VERSION 5.8 ;
BUSBITCHARS "[]" ;
DIVIDERCHAR "/" ;
UNITS
    DATABASE MICRONS 1000 ;
END UNITS

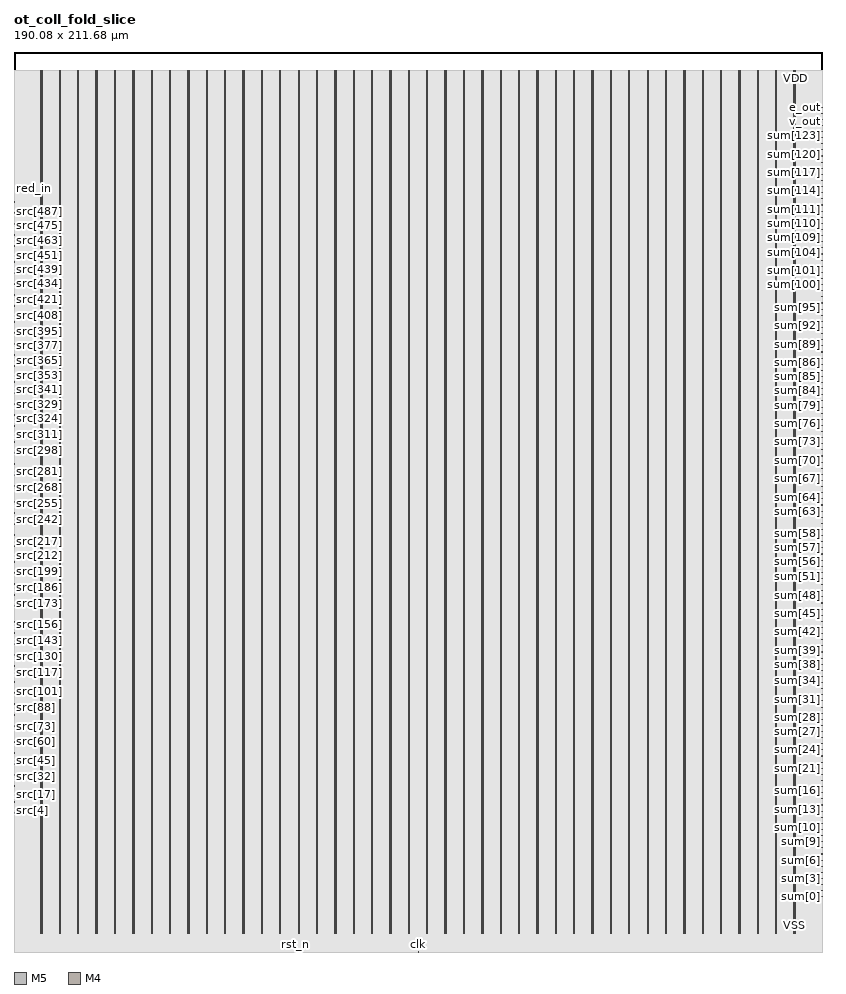
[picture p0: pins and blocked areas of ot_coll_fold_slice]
MACRO ot_coll_fold_slice
  FOREIGN ot_coll_fold_slice 0 0 ;
  CLASS BLOCK ;
  SIZE 190.08 BY 211.68 ;
  PIN clk
    DIRECTION INPUT ;
    USE SIGNAL ;
    PORT
      LAYER M5 ;
        RECT  95.04 0 95.064 0.084 ;
    END
  END clk
  PIN e_out
    DIRECTION OUTPUT ;
    USE SIGNAL ;
    PORT
      LAYER M4 ;
        RECT  189.996 198.72 190.08 198.744 ;
    END
  END e_out
  PIN red_in
    DIRECTION INPUT ;
    USE SIGNAL ;
    PORT
      LAYER M4 ;
        RECT  0 179.568 0.084 179.592 ;
    END
  END red_in
  PIN rst_n
    DIRECTION INPUT ;
    USE SIGNAL ;
    PORT
      LAYER M5 ;
        RECT  66.24 0 66.264 0.084 ;
    END
  END rst_n
  PIN src[0]
    DIRECTION INPUT ;
    USE SIGNAL ;
    PORT
      LAYER M4 ;
        RECT  0 32.112 0.084 32.136 ;
    END
  END src[0]
  PIN src[100]
    DIRECTION INPUT ;
    USE SIGNAL ;
    PORT
      LAYER M4 ;
        RECT  0 60.912 0.084 60.936 ;
    END
  END src[100]
  PIN src[101]
    DIRECTION INPUT ;
    USE SIGNAL ;
    PORT
      LAYER M4 ;
        RECT  0 61.2 0.084 61.224 ;
    END
  END src[101]
  PIN src[102]
    DIRECTION INPUT ;
    USE SIGNAL ;
    PORT
      LAYER M4 ;
        RECT  0 61.488 0.084 61.512 ;
    END
  END src[102]
  PIN src[103]
    DIRECTION INPUT ;
    USE SIGNAL ;
    PORT
      LAYER M4 ;
        RECT  0 61.776 0.084 61.8 ;
    END
  END src[103]
  PIN src[104]
    DIRECTION INPUT ;
    USE SIGNAL ;
    PORT
      LAYER M4 ;
        RECT  0 62.064 0.084 62.088 ;
    END
  END src[104]
  PIN src[105]
    DIRECTION INPUT ;
    USE SIGNAL ;
    PORT
      LAYER M4 ;
        RECT  0 62.352 0.084 62.376 ;
    END
  END src[105]
  PIN src[106]
    DIRECTION INPUT ;
    USE SIGNAL ;
    PORT
      LAYER M4 ;
        RECT  0 62.64 0.084 62.664 ;
    END
  END src[106]
  PIN src[107]
    DIRECTION INPUT ;
    USE SIGNAL ;
    PORT
      LAYER M4 ;
        RECT  0 62.928 0.084 62.952 ;
    END
  END src[107]
  PIN src[108]
    DIRECTION INPUT ;
    USE SIGNAL ;
    PORT
      LAYER M4 ;
        RECT  0 63.216 0.084 63.24 ;
    END
  END src[108]
  PIN src[109]
    DIRECTION INPUT ;
    USE SIGNAL ;
    PORT
      LAYER M4 ;
        RECT  0 63.504 0.084 63.528 ;
    END
  END src[109]
  PIN src[10]
    DIRECTION INPUT ;
    USE SIGNAL ;
    PORT
      LAYER M4 ;
        RECT  0 34.992 0.084 35.016 ;
    END
  END src[10]
  PIN src[110]
    DIRECTION INPUT ;
    USE SIGNAL ;
    PORT
      LAYER M4 ;
        RECT  0 63.792 0.084 63.816 ;
    END
  END src[110]
  PIN src[111]
    DIRECTION INPUT ;
    USE SIGNAL ;
    PORT
      LAYER M4 ;
        RECT  0 64.08 0.084 64.104 ;
    END
  END src[111]
  PIN src[112]
    DIRECTION INPUT ;
    USE SIGNAL ;
    PORT
      LAYER M4 ;
        RECT  0 64.368 0.084 64.392 ;
    END
  END src[112]
  PIN src[113]
    DIRECTION INPUT ;
    USE SIGNAL ;
    PORT
      LAYER M4 ;
        RECT  0 64.656 0.084 64.68 ;
    END
  END src[113]
  PIN src[114]
    DIRECTION INPUT ;
    USE SIGNAL ;
    PORT
      LAYER M4 ;
        RECT  0 64.944 0.084 64.968 ;
    END
  END src[114]
  PIN src[115]
    DIRECTION INPUT ;
    USE SIGNAL ;
    PORT
      LAYER M4 ;
        RECT  0 65.232 0.084 65.256 ;
    END
  END src[115]
  PIN src[116]
    DIRECTION INPUT ;
    USE SIGNAL ;
    PORT
      LAYER M4 ;
        RECT  0 65.52 0.084 65.544 ;
    END
  END src[116]
  PIN src[117]
    DIRECTION INPUT ;
    USE SIGNAL ;
    PORT
      LAYER M4 ;
        RECT  0 65.808 0.084 65.832 ;
    END
  END src[117]
  PIN src[118]
    DIRECTION INPUT ;
    USE SIGNAL ;
    PORT
      LAYER M4 ;
        RECT  0 66.096 0.084 66.12 ;
    END
  END src[118]
  PIN src[119]
    DIRECTION INPUT ;
    USE SIGNAL ;
    PORT
      LAYER M4 ;
        RECT  0 66.384 0.084 66.408 ;
    END
  END src[119]
  PIN src[11]
    DIRECTION INPUT ;
    USE SIGNAL ;
    PORT
      LAYER M4 ;
        RECT  0 35.28 0.084 35.304 ;
    END
  END src[11]
  PIN src[120]
    DIRECTION INPUT ;
    USE SIGNAL ;
    PORT
      LAYER M4 ;
        RECT  0 66.672 0.084 66.696 ;
    END
  END src[120]
  PIN src[121]
    DIRECTION INPUT ;
    USE SIGNAL ;
    PORT
      LAYER M4 ;
        RECT  0 66.96 0.084 66.984 ;
    END
  END src[121]
  PIN src[122]
    DIRECTION INPUT ;
    USE SIGNAL ;
    PORT
      LAYER M4 ;
        RECT  0 67.248 0.084 67.272 ;
    END
  END src[122]
  PIN src[123]
    DIRECTION INPUT ;
    USE SIGNAL ;
    PORT
      LAYER M4 ;
        RECT  0 67.536 0.084 67.56 ;
    END
  END src[123]
  PIN src[124]
    DIRECTION INPUT ;
    USE SIGNAL ;
    PORT
      LAYER M4 ;
        RECT  0 67.824 0.084 67.848 ;
    END
  END src[124]
  PIN src[125]
    DIRECTION INPUT ;
    USE SIGNAL ;
    PORT
      LAYER M4 ;
        RECT  0 68.112 0.084 68.136 ;
    END
  END src[125]
  PIN src[126]
    DIRECTION INPUT ;
    USE SIGNAL ;
    PORT
      LAYER M4 ;
        RECT  0 68.4 0.084 68.424 ;
    END
  END src[126]
  PIN src[127]
    DIRECTION INPUT ;
    USE SIGNAL ;
    PORT
      LAYER M4 ;
        RECT  0 68.688 0.084 68.712 ;
    END
  END src[127]
  PIN src[128]
    DIRECTION INPUT ;
    USE SIGNAL ;
    PORT
      LAYER M4 ;
        RECT  0 68.976 0.084 69 ;
    END
  END src[128]
  PIN src[129]
    DIRECTION INPUT ;
    USE SIGNAL ;
    PORT
      LAYER M4 ;
        RECT  0 69.264 0.084 69.288 ;
    END
  END src[129]
  PIN src[12]
    DIRECTION INPUT ;
    USE SIGNAL ;
    PORT
      LAYER M4 ;
        RECT  0 35.568 0.084 35.592 ;
    END
  END src[12]
  PIN src[130]
    DIRECTION INPUT ;
    USE SIGNAL ;
    PORT
      LAYER M4 ;
        RECT  0 69.552 0.084 69.576 ;
    END
  END src[130]
  PIN src[131]
    DIRECTION INPUT ;
    USE SIGNAL ;
    PORT
      LAYER M4 ;
        RECT  0 69.84 0.084 69.864 ;
    END
  END src[131]
  PIN src[132]
    DIRECTION INPUT ;
    USE SIGNAL ;
    PORT
      LAYER M4 ;
        RECT  0 70.128 0.084 70.152 ;
    END
  END src[132]
  PIN src[133]
    DIRECTION INPUT ;
    USE SIGNAL ;
    PORT
      LAYER M4 ;
        RECT  0 70.416 0.084 70.44 ;
    END
  END src[133]
  PIN src[134]
    DIRECTION INPUT ;
    USE SIGNAL ;
    PORT
      LAYER M4 ;
        RECT  0 70.704 0.084 70.728 ;
    END
  END src[134]
  PIN src[135]
    DIRECTION INPUT ;
    USE SIGNAL ;
    PORT
      LAYER M4 ;
        RECT  0 70.992 0.084 71.016 ;
    END
  END src[135]
  PIN src[136]
    DIRECTION INPUT ;
    USE SIGNAL ;
    PORT
      LAYER M4 ;
        RECT  0 71.28 0.084 71.304 ;
    END
  END src[136]
  PIN src[137]
    DIRECTION INPUT ;
    USE SIGNAL ;
    PORT
      LAYER M4 ;
        RECT  0 71.568 0.084 71.592 ;
    END
  END src[137]
  PIN src[138]
    DIRECTION INPUT ;
    USE SIGNAL ;
    PORT
      LAYER M4 ;
        RECT  0 71.856 0.084 71.88 ;
    END
  END src[138]
  PIN src[139]
    DIRECTION INPUT ;
    USE SIGNAL ;
    PORT
      LAYER M4 ;
        RECT  0 72.144 0.084 72.168 ;
    END
  END src[139]
  PIN src[13]
    DIRECTION INPUT ;
    USE SIGNAL ;
    PORT
      LAYER M4 ;
        RECT  0 35.856 0.084 35.88 ;
    END
  END src[13]
  PIN src[140]
    DIRECTION INPUT ;
    USE SIGNAL ;
    PORT
      LAYER M4 ;
        RECT  0 72.432 0.084 72.456 ;
    END
  END src[140]
  PIN src[141]
    DIRECTION INPUT ;
    USE SIGNAL ;
    PORT
      LAYER M4 ;
        RECT  0 72.72 0.084 72.744 ;
    END
  END src[141]
  PIN src[142]
    DIRECTION INPUT ;
    USE SIGNAL ;
    PORT
      LAYER M4 ;
        RECT  0 73.008 0.084 73.032 ;
    END
  END src[142]
  PIN src[143]
    DIRECTION INPUT ;
    USE SIGNAL ;
    PORT
      LAYER M4 ;
        RECT  0 73.296 0.084 73.32 ;
    END
  END src[143]
  PIN src[144]
    DIRECTION INPUT ;
    USE SIGNAL ;
    PORT
      LAYER M4 ;
        RECT  0 73.584 0.084 73.608 ;
    END
  END src[144]
  PIN src[145]
    DIRECTION INPUT ;
    USE SIGNAL ;
    PORT
      LAYER M4 ;
        RECT  0 73.872 0.084 73.896 ;
    END
  END src[145]
  PIN src[146]
    DIRECTION INPUT ;
    USE SIGNAL ;
    PORT
      LAYER M4 ;
        RECT  0 74.16 0.084 74.184 ;
    END
  END src[146]
  PIN src[147]
    DIRECTION INPUT ;
    USE SIGNAL ;
    PORT
      LAYER M4 ;
        RECT  0 74.448 0.084 74.472 ;
    END
  END src[147]
  PIN src[148]
    DIRECTION INPUT ;
    USE SIGNAL ;
    PORT
      LAYER M4 ;
        RECT  0 74.736 0.084 74.76 ;
    END
  END src[148]
  PIN src[149]
    DIRECTION INPUT ;
    USE SIGNAL ;
    PORT
      LAYER M4 ;
        RECT  0 75.024 0.084 75.048 ;
    END
  END src[149]
  PIN src[14]
    DIRECTION INPUT ;
    USE SIGNAL ;
    PORT
      LAYER M4 ;
        RECT  0 36.144 0.084 36.168 ;
    END
  END src[14]
  PIN src[150]
    DIRECTION INPUT ;
    USE SIGNAL ;
    PORT
      LAYER M4 ;
        RECT  0 75.312 0.084 75.336 ;
    END
  END src[150]
  PIN src[151]
    DIRECTION INPUT ;
    USE SIGNAL ;
    PORT
      LAYER M4 ;
        RECT  0 75.6 0.084 75.624 ;
    END
  END src[151]
  PIN src[152]
    DIRECTION INPUT ;
    USE SIGNAL ;
    PORT
      LAYER M4 ;
        RECT  0 75.888 0.084 75.912 ;
    END
  END src[152]
  PIN src[153]
    DIRECTION INPUT ;
    USE SIGNAL ;
    PORT
      LAYER M4 ;
        RECT  0 76.176 0.084 76.2 ;
    END
  END src[153]
  PIN src[154]
    DIRECTION INPUT ;
    USE SIGNAL ;
    PORT
      LAYER M4 ;
        RECT  0 76.464 0.084 76.488 ;
    END
  END src[154]
  PIN src[155]
    DIRECTION INPUT ;
    USE SIGNAL ;
    PORT
      LAYER M4 ;
        RECT  0 76.752 0.084 76.776 ;
    END
  END src[155]
  PIN src[156]
    DIRECTION INPUT ;
    USE SIGNAL ;
    PORT
      LAYER M4 ;
        RECT  0 77.04 0.084 77.064 ;
    END
  END src[156]
  PIN src[157]
    DIRECTION INPUT ;
    USE SIGNAL ;
    PORT
      LAYER M4 ;
        RECT  0 77.328 0.084 77.352 ;
    END
  END src[157]
  PIN src[158]
    DIRECTION INPUT ;
    USE SIGNAL ;
    PORT
      LAYER M4 ;
        RECT  0 77.616 0.084 77.64 ;
    END
  END src[158]
  PIN src[159]
    DIRECTION INPUT ;
    USE SIGNAL ;
    PORT
      LAYER M4 ;
        RECT  0 77.904 0.084 77.928 ;
    END
  END src[159]
  PIN src[15]
    DIRECTION INPUT ;
    USE SIGNAL ;
    PORT
      LAYER M4 ;
        RECT  0 36.432 0.084 36.456 ;
    END
  END src[15]
  PIN src[160]
    DIRECTION INPUT ;
    USE SIGNAL ;
    PORT
      LAYER M4 ;
        RECT  0 78.192 0.084 78.216 ;
    END
  END src[160]
  PIN src[161]
    DIRECTION INPUT ;
    USE SIGNAL ;
    PORT
      LAYER M4 ;
        RECT  0 78.48 0.084 78.504 ;
    END
  END src[161]
  PIN src[162]
    DIRECTION INPUT ;
    USE SIGNAL ;
    PORT
      LAYER M4 ;
        RECT  0 78.768 0.084 78.792 ;
    END
  END src[162]
  PIN src[163]
    DIRECTION INPUT ;
    USE SIGNAL ;
    PORT
      LAYER M4 ;
        RECT  0 79.056 0.084 79.08 ;
    END
  END src[163]
  PIN src[164]
    DIRECTION INPUT ;
    USE SIGNAL ;
    PORT
      LAYER M4 ;
        RECT  0 79.344 0.084 79.368 ;
    END
  END src[164]
  PIN src[165]
    DIRECTION INPUT ;
    USE SIGNAL ;
    PORT
      LAYER M4 ;
        RECT  0 79.632 0.084 79.656 ;
    END
  END src[165]
  PIN src[166]
    DIRECTION INPUT ;
    USE SIGNAL ;
    PORT
      LAYER M4 ;
        RECT  0 79.92 0.084 79.944 ;
    END
  END src[166]
  PIN src[167]
    DIRECTION INPUT ;
    USE SIGNAL ;
    PORT
      LAYER M4 ;
        RECT  0 80.208 0.084 80.232 ;
    END
  END src[167]
  PIN src[168]
    DIRECTION INPUT ;
    USE SIGNAL ;
    PORT
      LAYER M4 ;
        RECT  0 80.496 0.084 80.52 ;
    END
  END src[168]
  PIN src[169]
    DIRECTION INPUT ;
    USE SIGNAL ;
    PORT
      LAYER M4 ;
        RECT  0 80.784 0.084 80.808 ;
    END
  END src[169]
  PIN src[16]
    DIRECTION INPUT ;
    USE SIGNAL ;
    PORT
      LAYER M4 ;
        RECT  0 36.72 0.084 36.744 ;
    END
  END src[16]
  PIN src[170]
    DIRECTION INPUT ;
    USE SIGNAL ;
    PORT
      LAYER M4 ;
        RECT  0 81.072 0.084 81.096 ;
    END
  END src[170]
  PIN src[171]
    DIRECTION INPUT ;
    USE SIGNAL ;
    PORT
      LAYER M4 ;
        RECT  0 81.36 0.084 81.384 ;
    END
  END src[171]
  PIN src[172]
    DIRECTION INPUT ;
    USE SIGNAL ;
    PORT
      LAYER M4 ;
        RECT  0 81.648 0.084 81.672 ;
    END
  END src[172]
  PIN src[173]
    DIRECTION INPUT ;
    USE SIGNAL ;
    PORT
      LAYER M4 ;
        RECT  0 81.936 0.084 81.96 ;
    END
  END src[173]
  PIN src[174]
    DIRECTION INPUT ;
    USE SIGNAL ;
    PORT
      LAYER M4 ;
        RECT  0 82.224 0.084 82.248 ;
    END
  END src[174]
  PIN src[175]
    DIRECTION INPUT ;
    USE SIGNAL ;
    PORT
      LAYER M4 ;
        RECT  0 82.512 0.084 82.536 ;
    END
  END src[175]
  PIN src[176]
    DIRECTION INPUT ;
    USE SIGNAL ;
    PORT
      LAYER M4 ;
        RECT  0 82.8 0.084 82.824 ;
    END
  END src[176]
  PIN src[177]
    DIRECTION INPUT ;
    USE SIGNAL ;
    PORT
      LAYER M4 ;
        RECT  0 83.088 0.084 83.112 ;
    END
  END src[177]
  PIN src[178]
    DIRECTION INPUT ;
    USE SIGNAL ;
    PORT
      LAYER M4 ;
        RECT  0 83.376 0.084 83.4 ;
    END
  END src[178]
  PIN src[179]
    DIRECTION INPUT ;
    USE SIGNAL ;
    PORT
      LAYER M4 ;
        RECT  0 83.664 0.084 83.688 ;
    END
  END src[179]
  PIN src[17]
    DIRECTION INPUT ;
    USE SIGNAL ;
    PORT
      LAYER M4 ;
        RECT  0 37.008 0.084 37.032 ;
    END
  END src[17]
  PIN src[180]
    DIRECTION INPUT ;
    USE SIGNAL ;
    PORT
      LAYER M4 ;
        RECT  0 83.952 0.084 83.976 ;
    END
  END src[180]
  PIN src[181]
    DIRECTION INPUT ;
    USE SIGNAL ;
    PORT
      LAYER M4 ;
        RECT  0 84.24 0.084 84.264 ;
    END
  END src[181]
  PIN src[182]
    DIRECTION INPUT ;
    USE SIGNAL ;
    PORT
      LAYER M4 ;
        RECT  0 84.528 0.084 84.552 ;
    END
  END src[182]
  PIN src[183]
    DIRECTION INPUT ;
    USE SIGNAL ;
    PORT
      LAYER M4 ;
        RECT  0 84.816 0.084 84.84 ;
    END
  END src[183]
  PIN src[184]
    DIRECTION INPUT ;
    USE SIGNAL ;
    PORT
      LAYER M4 ;
        RECT  0 85.104 0.084 85.128 ;
    END
  END src[184]
  PIN src[185]
    DIRECTION INPUT ;
    USE SIGNAL ;
    PORT
      LAYER M4 ;
        RECT  0 85.392 0.084 85.416 ;
    END
  END src[185]
  PIN src[186]
    DIRECTION INPUT ;
    USE SIGNAL ;
    PORT
      LAYER M4 ;
        RECT  0 85.68 0.084 85.704 ;
    END
  END src[186]
  PIN src[187]
    DIRECTION INPUT ;
    USE SIGNAL ;
    PORT
      LAYER M4 ;
        RECT  0 85.968 0.084 85.992 ;
    END
  END src[187]
  PIN src[188]
    DIRECTION INPUT ;
    USE SIGNAL ;
    PORT
      LAYER M4 ;
        RECT  0 86.256 0.084 86.28 ;
    END
  END src[188]
  PIN src[189]
    DIRECTION INPUT ;
    USE SIGNAL ;
    PORT
      LAYER M4 ;
        RECT  0 86.544 0.084 86.568 ;
    END
  END src[189]
  PIN src[18]
    DIRECTION INPUT ;
    USE SIGNAL ;
    PORT
      LAYER M4 ;
        RECT  0 37.296 0.084 37.32 ;
    END
  END src[18]
  PIN src[190]
    DIRECTION INPUT ;
    USE SIGNAL ;
    PORT
      LAYER M4 ;
        RECT  0 86.832 0.084 86.856 ;
    END
  END src[190]
  PIN src[191]
    DIRECTION INPUT ;
    USE SIGNAL ;
    PORT
      LAYER M4 ;
        RECT  0 87.12 0.084 87.144 ;
    END
  END src[191]
  PIN src[192]
    DIRECTION INPUT ;
    USE SIGNAL ;
    PORT
      LAYER M4 ;
        RECT  0 87.408 0.084 87.432 ;
    END
  END src[192]
  PIN src[193]
    DIRECTION INPUT ;
    USE SIGNAL ;
    PORT
      LAYER M4 ;
        RECT  0 87.696 0.084 87.72 ;
    END
  END src[193]
  PIN src[194]
    DIRECTION INPUT ;
    USE SIGNAL ;
    PORT
      LAYER M4 ;
        RECT  0 87.984 0.084 88.008 ;
    END
  END src[194]
  PIN src[195]
    DIRECTION INPUT ;
    USE SIGNAL ;
    PORT
      LAYER M4 ;
        RECT  0 88.272 0.084 88.296 ;
    END
  END src[195]
  PIN src[196]
    DIRECTION INPUT ;
    USE SIGNAL ;
    PORT
      LAYER M4 ;
        RECT  0 88.56 0.084 88.584 ;
    END
  END src[196]
  PIN src[197]
    DIRECTION INPUT ;
    USE SIGNAL ;
    PORT
      LAYER M4 ;
        RECT  0 88.848 0.084 88.872 ;
    END
  END src[197]
  PIN src[198]
    DIRECTION INPUT ;
    USE SIGNAL ;
    PORT
      LAYER M4 ;
        RECT  0 89.136 0.084 89.16 ;
    END
  END src[198]
  PIN src[199]
    DIRECTION INPUT ;
    USE SIGNAL ;
    PORT
      LAYER M4 ;
        RECT  0 89.424 0.084 89.448 ;
    END
  END src[199]
  PIN src[19]
    DIRECTION INPUT ;
    USE SIGNAL ;
    PORT
      LAYER M4 ;
        RECT  0 37.584 0.084 37.608 ;
    END
  END src[19]
  PIN src[1]
    DIRECTION INPUT ;
    USE SIGNAL ;
    PORT
      LAYER M4 ;
        RECT  0 32.4 0.084 32.424 ;
    END
  END src[1]
  PIN src[200]
    DIRECTION INPUT ;
    USE SIGNAL ;
    PORT
      LAYER M4 ;
        RECT  0 89.712 0.084 89.736 ;
    END
  END src[200]
  PIN src[201]
    DIRECTION INPUT ;
    USE SIGNAL ;
    PORT
      LAYER M4 ;
        RECT  0 90 0.084 90.024 ;
    END
  END src[201]
  PIN src[202]
    DIRECTION INPUT ;
    USE SIGNAL ;
    PORT
      LAYER M4 ;
        RECT  0 90.288 0.084 90.312 ;
    END
  END src[202]
  PIN src[203]
    DIRECTION INPUT ;
    USE SIGNAL ;
    PORT
      LAYER M4 ;
        RECT  0 90.576 0.084 90.6 ;
    END
  END src[203]
  PIN src[204]
    DIRECTION INPUT ;
    USE SIGNAL ;
    PORT
      LAYER M4 ;
        RECT  0 90.864 0.084 90.888 ;
    END
  END src[204]
  PIN src[205]
    DIRECTION INPUT ;
    USE SIGNAL ;
    PORT
      LAYER M4 ;
        RECT  0 91.152 0.084 91.176 ;
    END
  END src[205]
  PIN src[206]
    DIRECTION INPUT ;
    USE SIGNAL ;
    PORT
      LAYER M4 ;
        RECT  0 91.44 0.084 91.464 ;
    END
  END src[206]
  PIN src[207]
    DIRECTION INPUT ;
    USE SIGNAL ;
    PORT
      LAYER M4 ;
        RECT  0 91.728 0.084 91.752 ;
    END
  END src[207]
  PIN src[208]
    DIRECTION INPUT ;
    USE SIGNAL ;
    PORT
      LAYER M4 ;
        RECT  0 92.016 0.084 92.04 ;
    END
  END src[208]
  PIN src[209]
    DIRECTION INPUT ;
    USE SIGNAL ;
    PORT
      LAYER M4 ;
        RECT  0 92.304 0.084 92.328 ;
    END
  END src[209]
  PIN src[20]
    DIRECTION INPUT ;
    USE SIGNAL ;
    PORT
      LAYER M4 ;
        RECT  0 37.872 0.084 37.896 ;
    END
  END src[20]
  PIN src[210]
    DIRECTION INPUT ;
    USE SIGNAL ;
    PORT
      LAYER M4 ;
        RECT  0 92.592 0.084 92.616 ;
    END
  END src[210]
  PIN src[211]
    DIRECTION INPUT ;
    USE SIGNAL ;
    PORT
      LAYER M4 ;
        RECT  0 92.88 0.084 92.904 ;
    END
  END src[211]
  PIN src[212]
    DIRECTION INPUT ;
    USE SIGNAL ;
    PORT
      LAYER M4 ;
        RECT  0 93.168 0.084 93.192 ;
    END
  END src[212]
  PIN src[213]
    DIRECTION INPUT ;
    USE SIGNAL ;
    PORT
      LAYER M4 ;
        RECT  0 93.456 0.084 93.48 ;
    END
  END src[213]
  PIN src[214]
    DIRECTION INPUT ;
    USE SIGNAL ;
    PORT
      LAYER M4 ;
        RECT  0 93.744 0.084 93.768 ;
    END
  END src[214]
  PIN src[215]
    DIRECTION INPUT ;
    USE SIGNAL ;
    PORT
      LAYER M4 ;
        RECT  0 94.032 0.084 94.056 ;
    END
  END src[215]
  PIN src[216]
    DIRECTION INPUT ;
    USE SIGNAL ;
    PORT
      LAYER M4 ;
        RECT  0 94.32 0.084 94.344 ;
    END
  END src[216]
  PIN src[217]
    DIRECTION INPUT ;
    USE SIGNAL ;
    PORT
      LAYER M4 ;
        RECT  0 94.608 0.084 94.632 ;
    END
  END src[217]
  PIN src[218]
    DIRECTION INPUT ;
    USE SIGNAL ;
    PORT
      LAYER M4 ;
        RECT  0 94.896 0.084 94.92 ;
    END
  END src[218]
  PIN src[219]
    DIRECTION INPUT ;
    USE SIGNAL ;
    PORT
      LAYER M4 ;
        RECT  0 95.184 0.084 95.208 ;
    END
  END src[219]
  PIN src[21]
    DIRECTION INPUT ;
    USE SIGNAL ;
    PORT
      LAYER M4 ;
        RECT  0 38.16 0.084 38.184 ;
    END
  END src[21]
  PIN src[220]
    DIRECTION INPUT ;
    USE SIGNAL ;
    PORT
      LAYER M4 ;
        RECT  0 95.472 0.084 95.496 ;
    END
  END src[220]
  PIN src[221]
    DIRECTION INPUT ;
    USE SIGNAL ;
    PORT
      LAYER M4 ;
        RECT  0 95.76 0.084 95.784 ;
    END
  END src[221]
  PIN src[222]
    DIRECTION INPUT ;
    USE SIGNAL ;
    PORT
      LAYER M4 ;
        RECT  0 96.048 0.084 96.072 ;
    END
  END src[222]
  PIN src[223]
    DIRECTION INPUT ;
    USE SIGNAL ;
    PORT
      LAYER M4 ;
        RECT  0 96.336 0.084 96.36 ;
    END
  END src[223]
  PIN src[224]
    DIRECTION INPUT ;
    USE SIGNAL ;
    PORT
      LAYER M4 ;
        RECT  0 96.624 0.084 96.648 ;
    END
  END src[224]
  PIN src[225]
    DIRECTION INPUT ;
    USE SIGNAL ;
    PORT
      LAYER M4 ;
        RECT  0 96.912 0.084 96.936 ;
    END
  END src[225]
  PIN src[226]
    DIRECTION INPUT ;
    USE SIGNAL ;
    PORT
      LAYER M4 ;
        RECT  0 97.2 0.084 97.224 ;
    END
  END src[226]
  PIN src[227]
    DIRECTION INPUT ;
    USE SIGNAL ;
    PORT
      LAYER M4 ;
        RECT  0 97.488 0.084 97.512 ;
    END
  END src[227]
  PIN src[228]
    DIRECTION INPUT ;
    USE SIGNAL ;
    PORT
      LAYER M4 ;
        RECT  0 97.776 0.084 97.8 ;
    END
  END src[228]
  PIN src[229]
    DIRECTION INPUT ;
    USE SIGNAL ;
    PORT
      LAYER M4 ;
        RECT  0 98.064 0.084 98.088 ;
    END
  END src[229]
  PIN src[22]
    DIRECTION INPUT ;
    USE SIGNAL ;
    PORT
      LAYER M4 ;
        RECT  0 38.448 0.084 38.472 ;
    END
  END src[22]
  PIN src[230]
    DIRECTION INPUT ;
    USE SIGNAL ;
    PORT
      LAYER M4 ;
        RECT  0 98.352 0.084 98.376 ;
    END
  END src[230]
  PIN src[231]
    DIRECTION INPUT ;
    USE SIGNAL ;
    PORT
      LAYER M4 ;
        RECT  0 98.64 0.084 98.664 ;
    END
  END src[231]
  PIN src[232]
    DIRECTION INPUT ;
    USE SIGNAL ;
    PORT
      LAYER M4 ;
        RECT  0 98.928 0.084 98.952 ;
    END
  END src[232]
  PIN src[233]
    DIRECTION INPUT ;
    USE SIGNAL ;
    PORT
      LAYER M4 ;
        RECT  0 99.216 0.084 99.24 ;
    END
  END src[233]
  PIN src[234]
    DIRECTION INPUT ;
    USE SIGNAL ;
    PORT
      LAYER M4 ;
        RECT  0 99.504 0.084 99.528 ;
    END
  END src[234]
  PIN src[235]
    DIRECTION INPUT ;
    USE SIGNAL ;
    PORT
      LAYER M4 ;
        RECT  0 99.792 0.084 99.816 ;
    END
  END src[235]
  PIN src[236]
    DIRECTION INPUT ;
    USE SIGNAL ;
    PORT
      LAYER M4 ;
        RECT  0 100.08 0.084 100.104 ;
    END
  END src[236]
  PIN src[237]
    DIRECTION INPUT ;
    USE SIGNAL ;
    PORT
      LAYER M4 ;
        RECT  0 100.368 0.084 100.392 ;
    END
  END src[237]
  PIN src[238]
    DIRECTION INPUT ;
    USE SIGNAL ;
    PORT
      LAYER M4 ;
        RECT  0 100.656 0.084 100.68 ;
    END
  END src[238]
  PIN src[239]
    DIRECTION INPUT ;
    USE SIGNAL ;
    PORT
      LAYER M4 ;
        RECT  0 100.944 0.084 100.968 ;
    END
  END src[239]
  PIN src[23]
    DIRECTION INPUT ;
    USE SIGNAL ;
    PORT
      LAYER M4 ;
        RECT  0 38.736 0.084 38.76 ;
    END
  END src[23]
  PIN src[240]
    DIRECTION INPUT ;
    USE SIGNAL ;
    PORT
      LAYER M4 ;
        RECT  0 101.232 0.084 101.256 ;
    END
  END src[240]
  PIN src[241]
    DIRECTION INPUT ;
    USE SIGNAL ;
    PORT
      LAYER M4 ;
        RECT  0 101.52 0.084 101.544 ;
    END
  END src[241]
  PIN src[242]
    DIRECTION INPUT ;
    USE SIGNAL ;
    PORT
      LAYER M4 ;
        RECT  0 101.808 0.084 101.832 ;
    END
  END src[242]
  PIN src[243]
    DIRECTION INPUT ;
    USE SIGNAL ;
    PORT
      LAYER M4 ;
        RECT  0 102.096 0.084 102.12 ;
    END
  END src[243]
  PIN src[244]
    DIRECTION INPUT ;
    USE SIGNAL ;
    PORT
      LAYER M4 ;
        RECT  0 102.384 0.084 102.408 ;
    END
  END src[244]
  PIN src[245]
    DIRECTION INPUT ;
    USE SIGNAL ;
    PORT
      LAYER M4 ;
        RECT  0 102.672 0.084 102.696 ;
    END
  END src[245]
  PIN src[246]
    DIRECTION INPUT ;
    USE SIGNAL ;
    PORT
      LAYER M4 ;
        RECT  0 102.96 0.084 102.984 ;
    END
  END src[246]
  PIN src[247]
    DIRECTION INPUT ;
    USE SIGNAL ;
    PORT
      LAYER M4 ;
        RECT  0 103.248 0.084 103.272 ;
    END
  END src[247]
  PIN src[248]
    DIRECTION INPUT ;
    USE SIGNAL ;
    PORT
      LAYER M4 ;
        RECT  0 103.536 0.084 103.56 ;
    END
  END src[248]
  PIN src[249]
    DIRECTION INPUT ;
    USE SIGNAL ;
    PORT
      LAYER M4 ;
        RECT  0 103.824 0.084 103.848 ;
    END
  END src[249]
  PIN src[24]
    DIRECTION INPUT ;
    USE SIGNAL ;
    PORT
      LAYER M4 ;
        RECT  0 39.024 0.084 39.048 ;
    END
  END src[24]
  PIN src[250]
    DIRECTION INPUT ;
    USE SIGNAL ;
    PORT
      LAYER M4 ;
        RECT  0 104.112 0.084 104.136 ;
    END
  END src[250]
  PIN src[251]
    DIRECTION INPUT ;
    USE SIGNAL ;
    PORT
      LAYER M4 ;
        RECT  0 104.4 0.084 104.424 ;
    END
  END src[251]
  PIN src[252]
    DIRECTION INPUT ;
    USE SIGNAL ;
    PORT
      LAYER M4 ;
        RECT  0 104.688 0.084 104.712 ;
    END
  END src[252]
  PIN src[253]
    DIRECTION INPUT ;
    USE SIGNAL ;
    PORT
      LAYER M4 ;
        RECT  0 104.976 0.084 105 ;
    END
  END src[253]
  PIN src[254]
    DIRECTION INPUT ;
    USE SIGNAL ;
    PORT
      LAYER M4 ;
        RECT  0 105.264 0.084 105.288 ;
    END
  END src[254]
  PIN src[255]
    DIRECTION INPUT ;
    USE SIGNAL ;
    PORT
      LAYER M4 ;
        RECT  0 105.552 0.084 105.576 ;
    END
  END src[255]
  PIN src[256]
    DIRECTION INPUT ;
    USE SIGNAL ;
    PORT
      LAYER M4 ;
        RECT  0 105.84 0.084 105.864 ;
    END
  END src[256]
  PIN src[257]
    DIRECTION INPUT ;
    USE SIGNAL ;
    PORT
      LAYER M4 ;
        RECT  0 106.128 0.084 106.152 ;
    END
  END src[257]
  PIN src[258]
    DIRECTION INPUT ;
    USE SIGNAL ;
    PORT
      LAYER M4 ;
        RECT  0 106.416 0.084 106.44 ;
    END
  END src[258]
  PIN src[259]
    DIRECTION INPUT ;
    USE SIGNAL ;
    PORT
      LAYER M4 ;
        RECT  0 106.704 0.084 106.728 ;
    END
  END src[259]
  PIN src[25]
    DIRECTION INPUT ;
    USE SIGNAL ;
    PORT
      LAYER M4 ;
        RECT  0 39.312 0.084 39.336 ;
    END
  END src[25]
  PIN src[260]
    DIRECTION INPUT ;
    USE SIGNAL ;
    PORT
      LAYER M4 ;
        RECT  0 106.992 0.084 107.016 ;
    END
  END src[260]
  PIN src[261]
    DIRECTION INPUT ;
    USE SIGNAL ;
    PORT
      LAYER M4 ;
        RECT  0 107.28 0.084 107.304 ;
    END
  END src[261]
  PIN src[262]
    DIRECTION INPUT ;
    USE SIGNAL ;
    PORT
      LAYER M4 ;
        RECT  0 107.568 0.084 107.592 ;
    END
  END src[262]
  PIN src[263]
    DIRECTION INPUT ;
    USE SIGNAL ;
    PORT
      LAYER M4 ;
        RECT  0 107.856 0.084 107.88 ;
    END
  END src[263]
  PIN src[264]
    DIRECTION INPUT ;
    USE SIGNAL ;
    PORT
      LAYER M4 ;
        RECT  0 108.144 0.084 108.168 ;
    END
  END src[264]
  PIN src[265]
    DIRECTION INPUT ;
    USE SIGNAL ;
    PORT
      LAYER M4 ;
        RECT  0 108.432 0.084 108.456 ;
    END
  END src[265]
  PIN src[266]
    DIRECTION INPUT ;
    USE SIGNAL ;
    PORT
      LAYER M4 ;
        RECT  0 108.72 0.084 108.744 ;
    END
  END src[266]
  PIN src[267]
    DIRECTION INPUT ;
    USE SIGNAL ;
    PORT
      LAYER M4 ;
        RECT  0 109.008 0.084 109.032 ;
    END
  END src[267]
  PIN src[268]
    DIRECTION INPUT ;
    USE SIGNAL ;
    PORT
      LAYER M4 ;
        RECT  0 109.296 0.084 109.32 ;
    END
  END src[268]
  PIN src[269]
    DIRECTION INPUT ;
    USE SIGNAL ;
    PORT
      LAYER M4 ;
        RECT  0 109.584 0.084 109.608 ;
    END
  END src[269]
  PIN src[26]
    DIRECTION INPUT ;
    USE SIGNAL ;
    PORT
      LAYER M4 ;
        RECT  0 39.6 0.084 39.624 ;
    END
  END src[26]
  PIN src[270]
    DIRECTION INPUT ;
    USE SIGNAL ;
    PORT
      LAYER M4 ;
        RECT  0 109.872 0.084 109.896 ;
    END
  END src[270]
  PIN src[271]
    DIRECTION INPUT ;
    USE SIGNAL ;
    PORT
      LAYER M4 ;
        RECT  0 110.16 0.084 110.184 ;
    END
  END src[271]
  PIN src[272]
    DIRECTION INPUT ;
    USE SIGNAL ;
    PORT
      LAYER M4 ;
        RECT  0 110.448 0.084 110.472 ;
    END
  END src[272]
  PIN src[273]
    DIRECTION INPUT ;
    USE SIGNAL ;
    PORT
      LAYER M4 ;
        RECT  0 110.736 0.084 110.76 ;
    END
  END src[273]
  PIN src[274]
    DIRECTION INPUT ;
    USE SIGNAL ;
    PORT
      LAYER M4 ;
        RECT  0 111.024 0.084 111.048 ;
    END
  END src[274]
  PIN src[275]
    DIRECTION INPUT ;
    USE SIGNAL ;
    PORT
      LAYER M4 ;
        RECT  0 111.312 0.084 111.336 ;
    END
  END src[275]
  PIN src[276]
    DIRECTION INPUT ;
    USE SIGNAL ;
    PORT
      LAYER M4 ;
        RECT  0 111.6 0.084 111.624 ;
    END
  END src[276]
  PIN src[277]
    DIRECTION INPUT ;
    USE SIGNAL ;
    PORT
      LAYER M4 ;
        RECT  0 111.888 0.084 111.912 ;
    END
  END src[277]
  PIN src[278]
    DIRECTION INPUT ;
    USE SIGNAL ;
    PORT
      LAYER M4 ;
        RECT  0 112.176 0.084 112.2 ;
    END
  END src[278]
  PIN src[279]
    DIRECTION INPUT ;
    USE SIGNAL ;
    PORT
      LAYER M4 ;
        RECT  0 112.464 0.084 112.488 ;
    END
  END src[279]
  PIN src[27]
    DIRECTION INPUT ;
    USE SIGNAL ;
    PORT
      LAYER M4 ;
        RECT  0 39.888 0.084 39.912 ;
    END
  END src[27]
  PIN src[280]
    DIRECTION INPUT ;
    USE SIGNAL ;
    PORT
      LAYER M4 ;
        RECT  0 112.752 0.084 112.776 ;
    END
  END src[280]
  PIN src[281]
    DIRECTION INPUT ;
    USE SIGNAL ;
    PORT
      LAYER M4 ;
        RECT  0 113.04 0.084 113.064 ;
    END
  END src[281]
  PIN src[282]
    DIRECTION INPUT ;
    USE SIGNAL ;
    PORT
      LAYER M4 ;
        RECT  0 113.328 0.084 113.352 ;
    END
  END src[282]
  PIN src[283]
    DIRECTION INPUT ;
    USE SIGNAL ;
    PORT
      LAYER M4 ;
        RECT  0 113.616 0.084 113.64 ;
    END
  END src[283]
  PIN src[284]
    DIRECTION INPUT ;
    USE SIGNAL ;
    PORT
      LAYER M4 ;
        RECT  0 113.904 0.084 113.928 ;
    END
  END src[284]
  PIN src[285]
    DIRECTION INPUT ;
    USE SIGNAL ;
    PORT
      LAYER M4 ;
        RECT  0 114.192 0.084 114.216 ;
    END
  END src[285]
  PIN src[286]
    DIRECTION INPUT ;
    USE SIGNAL ;
    PORT
      LAYER M4 ;
        RECT  0 114.48 0.084 114.504 ;
    END
  END src[286]
  PIN src[287]
    DIRECTION INPUT ;
    USE SIGNAL ;
    PORT
      LAYER M4 ;
        RECT  0 114.768 0.084 114.792 ;
    END
  END src[287]
  PIN src[288]
    DIRECTION INPUT ;
    USE SIGNAL ;
    PORT
      LAYER M4 ;
        RECT  0 115.056 0.084 115.08 ;
    END
  END src[288]
  PIN src[289]
    DIRECTION INPUT ;
    USE SIGNAL ;
    PORT
      LAYER M4 ;
        RECT  0 115.344 0.084 115.368 ;
    END
  END src[289]
  PIN src[28]
    DIRECTION INPUT ;
    USE SIGNAL ;
    PORT
      LAYER M4 ;
        RECT  0 40.176 0.084 40.2 ;
    END
  END src[28]
  PIN src[290]
    DIRECTION INPUT ;
    USE SIGNAL ;
    PORT
      LAYER M4 ;
        RECT  0 115.632 0.084 115.656 ;
    END
  END src[290]
  PIN src[291]
    DIRECTION INPUT ;
    USE SIGNAL ;
    PORT
      LAYER M4 ;
        RECT  0 115.92 0.084 115.944 ;
    END
  END src[291]
  PIN src[292]
    DIRECTION INPUT ;
    USE SIGNAL ;
    PORT
      LAYER M4 ;
        RECT  0 116.208 0.084 116.232 ;
    END
  END src[292]
  PIN src[293]
    DIRECTION INPUT ;
    USE SIGNAL ;
    PORT
      LAYER M4 ;
        RECT  0 116.496 0.084 116.52 ;
    END
  END src[293]
  PIN src[294]
    DIRECTION INPUT ;
    USE SIGNAL ;
    PORT
      LAYER M4 ;
        RECT  0 116.784 0.084 116.808 ;
    END
  END src[294]
  PIN src[295]
    DIRECTION INPUT ;
    USE SIGNAL ;
    PORT
      LAYER M4 ;
        RECT  0 117.072 0.084 117.096 ;
    END
  END src[295]
  PIN src[296]
    DIRECTION INPUT ;
    USE SIGNAL ;
    PORT
      LAYER M4 ;
        RECT  0 117.36 0.084 117.384 ;
    END
  END src[296]
  PIN src[297]
    DIRECTION INPUT ;
    USE SIGNAL ;
    PORT
      LAYER M4 ;
        RECT  0 117.648 0.084 117.672 ;
    END
  END src[297]
  PIN src[298]
    DIRECTION INPUT ;
    USE SIGNAL ;
    PORT
      LAYER M4 ;
        RECT  0 117.936 0.084 117.96 ;
    END
  END src[298]
  PIN src[299]
    DIRECTION INPUT ;
    USE SIGNAL ;
    PORT
      LAYER M4 ;
        RECT  0 118.224 0.084 118.248 ;
    END
  END src[299]
  PIN src[29]
    DIRECTION INPUT ;
    USE SIGNAL ;
    PORT
      LAYER M4 ;
        RECT  0 40.464 0.084 40.488 ;
    END
  END src[29]
  PIN src[2]
    DIRECTION INPUT ;
    USE SIGNAL ;
    PORT
      LAYER M4 ;
        RECT  0 32.688 0.084 32.712 ;
    END
  END src[2]
  PIN src[300]
    DIRECTION INPUT ;
    USE SIGNAL ;
    PORT
      LAYER M4 ;
        RECT  0 118.512 0.084 118.536 ;
    END
  END src[300]
  PIN src[301]
    DIRECTION INPUT ;
    USE SIGNAL ;
    PORT
      LAYER M4 ;
        RECT  0 118.8 0.084 118.824 ;
    END
  END src[301]
  PIN src[302]
    DIRECTION INPUT ;
    USE SIGNAL ;
    PORT
      LAYER M4 ;
        RECT  0 119.088 0.084 119.112 ;
    END
  END src[302]
  PIN src[303]
    DIRECTION INPUT ;
    USE SIGNAL ;
    PORT
      LAYER M4 ;
        RECT  0 119.376 0.084 119.4 ;
    END
  END src[303]
  PIN src[304]
    DIRECTION INPUT ;
    USE SIGNAL ;
    PORT
      LAYER M4 ;
        RECT  0 119.664 0.084 119.688 ;
    END
  END src[304]
  PIN src[305]
    DIRECTION INPUT ;
    USE SIGNAL ;
    PORT
      LAYER M4 ;
        RECT  0 119.952 0.084 119.976 ;
    END
  END src[305]
  PIN src[306]
    DIRECTION INPUT ;
    USE SIGNAL ;
    PORT
      LAYER M4 ;
        RECT  0 120.24 0.084 120.264 ;
    END
  END src[306]
  PIN src[307]
    DIRECTION INPUT ;
    USE SIGNAL ;
    PORT
      LAYER M4 ;
        RECT  0 120.528 0.084 120.552 ;
    END
  END src[307]
  PIN src[308]
    DIRECTION INPUT ;
    USE SIGNAL ;
    PORT
      LAYER M4 ;
        RECT  0 120.816 0.084 120.84 ;
    END
  END src[308]
  PIN src[309]
    DIRECTION INPUT ;
    USE SIGNAL ;
    PORT
      LAYER M4 ;
        RECT  0 121.104 0.084 121.128 ;
    END
  END src[309]
  PIN src[30]
    DIRECTION INPUT ;
    USE SIGNAL ;
    PORT
      LAYER M4 ;
        RECT  0 40.752 0.084 40.776 ;
    END
  END src[30]
  PIN src[310]
    DIRECTION INPUT ;
    USE SIGNAL ;
    PORT
      LAYER M4 ;
        RECT  0 121.392 0.084 121.416 ;
    END
  END src[310]
  PIN src[311]
    DIRECTION INPUT ;
    USE SIGNAL ;
    PORT
      LAYER M4 ;
        RECT  0 121.68 0.084 121.704 ;
    END
  END src[311]
  PIN src[312]
    DIRECTION INPUT ;
    USE SIGNAL ;
    PORT
      LAYER M4 ;
        RECT  0 121.968 0.084 121.992 ;
    END
  END src[312]
  PIN src[313]
    DIRECTION INPUT ;
    USE SIGNAL ;
    PORT
      LAYER M4 ;
        RECT  0 122.256 0.084 122.28 ;
    END
  END src[313]
  PIN src[314]
    DIRECTION INPUT ;
    USE SIGNAL ;
    PORT
      LAYER M4 ;
        RECT  0 122.544 0.084 122.568 ;
    END
  END src[314]
  PIN src[315]
    DIRECTION INPUT ;
    USE SIGNAL ;
    PORT
      LAYER M4 ;
        RECT  0 122.832 0.084 122.856 ;
    END
  END src[315]
  PIN src[316]
    DIRECTION INPUT ;
    USE SIGNAL ;
    PORT
      LAYER M4 ;
        RECT  0 123.12 0.084 123.144 ;
    END
  END src[316]
  PIN src[317]
    DIRECTION INPUT ;
    USE SIGNAL ;
    PORT
      LAYER M4 ;
        RECT  0 123.408 0.084 123.432 ;
    END
  END src[317]
  PIN src[318]
    DIRECTION INPUT ;
    USE SIGNAL ;
    PORT
      LAYER M4 ;
        RECT  0 123.696 0.084 123.72 ;
    END
  END src[318]
  PIN src[319]
    DIRECTION INPUT ;
    USE SIGNAL ;
    PORT
      LAYER M4 ;
        RECT  0 123.984 0.084 124.008 ;
    END
  END src[319]
  PIN src[31]
    DIRECTION INPUT ;
    USE SIGNAL ;
    PORT
      LAYER M4 ;
        RECT  0 41.04 0.084 41.064 ;
    END
  END src[31]
  PIN src[320]
    DIRECTION INPUT ;
    USE SIGNAL ;
    PORT
      LAYER M4 ;
        RECT  0 124.272 0.084 124.296 ;
    END
  END src[320]
  PIN src[321]
    DIRECTION INPUT ;
    USE SIGNAL ;
    PORT
      LAYER M4 ;
        RECT  0 124.56 0.084 124.584 ;
    END
  END src[321]
  PIN src[322]
    DIRECTION INPUT ;
    USE SIGNAL ;
    PORT
      LAYER M4 ;
        RECT  0 124.848 0.084 124.872 ;
    END
  END src[322]
  PIN src[323]
    DIRECTION INPUT ;
    USE SIGNAL ;
    PORT
      LAYER M4 ;
        RECT  0 125.136 0.084 125.16 ;
    END
  END src[323]
  PIN src[324]
    DIRECTION INPUT ;
    USE SIGNAL ;
    PORT
      LAYER M4 ;
        RECT  0 125.424 0.084 125.448 ;
    END
  END src[324]
  PIN src[325]
    DIRECTION INPUT ;
    USE SIGNAL ;
    PORT
      LAYER M4 ;
        RECT  0 125.712 0.084 125.736 ;
    END
  END src[325]
  PIN src[326]
    DIRECTION INPUT ;
    USE SIGNAL ;
    PORT
      LAYER M4 ;
        RECT  0 126 0.084 126.024 ;
    END
  END src[326]
  PIN src[327]
    DIRECTION INPUT ;
    USE SIGNAL ;
    PORT
      LAYER M4 ;
        RECT  0 126.288 0.084 126.312 ;
    END
  END src[327]
  PIN src[328]
    DIRECTION INPUT ;
    USE SIGNAL ;
    PORT
      LAYER M4 ;
        RECT  0 126.576 0.084 126.6 ;
    END
  END src[328]
  PIN src[329]
    DIRECTION INPUT ;
    USE SIGNAL ;
    PORT
      LAYER M4 ;
        RECT  0 126.864 0.084 126.888 ;
    END
  END src[329]
  PIN src[32]
    DIRECTION INPUT ;
    USE SIGNAL ;
    PORT
      LAYER M4 ;
        RECT  0 41.328 0.084 41.352 ;
    END
  END src[32]
  PIN src[330]
    DIRECTION INPUT ;
    USE SIGNAL ;
    PORT
      LAYER M4 ;
        RECT  0 127.152 0.084 127.176 ;
    END
  END src[330]
  PIN src[331]
    DIRECTION INPUT ;
    USE SIGNAL ;
    PORT
      LAYER M4 ;
        RECT  0 127.44 0.084 127.464 ;
    END
  END src[331]
  PIN src[332]
    DIRECTION INPUT ;
    USE SIGNAL ;
    PORT
      LAYER M4 ;
        RECT  0 127.728 0.084 127.752 ;
    END
  END src[332]
  PIN src[333]
    DIRECTION INPUT ;
    USE SIGNAL ;
    PORT
      LAYER M4 ;
        RECT  0 128.016 0.084 128.04 ;
    END
  END src[333]
  PIN src[334]
    DIRECTION INPUT ;
    USE SIGNAL ;
    PORT
      LAYER M4 ;
        RECT  0 128.304 0.084 128.328 ;
    END
  END src[334]
  PIN src[335]
    DIRECTION INPUT ;
    USE SIGNAL ;
    PORT
      LAYER M4 ;
        RECT  0 128.592 0.084 128.616 ;
    END
  END src[335]
  PIN src[336]
    DIRECTION INPUT ;
    USE SIGNAL ;
    PORT
      LAYER M4 ;
        RECT  0 128.88 0.084 128.904 ;
    END
  END src[336]
  PIN src[337]
    DIRECTION INPUT ;
    USE SIGNAL ;
    PORT
      LAYER M4 ;
        RECT  0 129.168 0.084 129.192 ;
    END
  END src[337]
  PIN src[338]
    DIRECTION INPUT ;
    USE SIGNAL ;
    PORT
      LAYER M4 ;
        RECT  0 129.456 0.084 129.48 ;
    END
  END src[338]
  PIN src[339]
    DIRECTION INPUT ;
    USE SIGNAL ;
    PORT
      LAYER M4 ;
        RECT  0 129.744 0.084 129.768 ;
    END
  END src[339]
  PIN src[33]
    DIRECTION INPUT ;
    USE SIGNAL ;
    PORT
      LAYER M4 ;
        RECT  0 41.616 0.084 41.64 ;
    END
  END src[33]
  PIN src[340]
    DIRECTION INPUT ;
    USE SIGNAL ;
    PORT
      LAYER M4 ;
        RECT  0 130.032 0.084 130.056 ;
    END
  END src[340]
  PIN src[341]
    DIRECTION INPUT ;
    USE SIGNAL ;
    PORT
      LAYER M4 ;
        RECT  0 130.32 0.084 130.344 ;
    END
  END src[341]
  PIN src[342]
    DIRECTION INPUT ;
    USE SIGNAL ;
    PORT
      LAYER M4 ;
        RECT  0 130.608 0.084 130.632 ;
    END
  END src[342]
  PIN src[343]
    DIRECTION INPUT ;
    USE SIGNAL ;
    PORT
      LAYER M4 ;
        RECT  0 130.896 0.084 130.92 ;
    END
  END src[343]
  PIN src[344]
    DIRECTION INPUT ;
    USE SIGNAL ;
    PORT
      LAYER M4 ;
        RECT  0 131.184 0.084 131.208 ;
    END
  END src[344]
  PIN src[345]
    DIRECTION INPUT ;
    USE SIGNAL ;
    PORT
      LAYER M4 ;
        RECT  0 131.472 0.084 131.496 ;
    END
  END src[345]
  PIN src[346]
    DIRECTION INPUT ;
    USE SIGNAL ;
    PORT
      LAYER M4 ;
        RECT  0 131.76 0.084 131.784 ;
    END
  END src[346]
  PIN src[347]
    DIRECTION INPUT ;
    USE SIGNAL ;
    PORT
      LAYER M4 ;
        RECT  0 132.048 0.084 132.072 ;
    END
  END src[347]
  PIN src[348]
    DIRECTION INPUT ;
    USE SIGNAL ;
    PORT
      LAYER M4 ;
        RECT  0 132.336 0.084 132.36 ;
    END
  END src[348]
  PIN src[349]
    DIRECTION INPUT ;
    USE SIGNAL ;
    PORT
      LAYER M4 ;
        RECT  0 132.624 0.084 132.648 ;
    END
  END src[349]
  PIN src[34]
    DIRECTION INPUT ;
    USE SIGNAL ;
    PORT
      LAYER M4 ;
        RECT  0 41.904 0.084 41.928 ;
    END
  END src[34]
  PIN src[350]
    DIRECTION INPUT ;
    USE SIGNAL ;
    PORT
      LAYER M4 ;
        RECT  0 132.912 0.084 132.936 ;
    END
  END src[350]
  PIN src[351]
    DIRECTION INPUT ;
    USE SIGNAL ;
    PORT
      LAYER M4 ;
        RECT  0 133.2 0.084 133.224 ;
    END
  END src[351]
  PIN src[352]
    DIRECTION INPUT ;
    USE SIGNAL ;
    PORT
      LAYER M4 ;
        RECT  0 133.488 0.084 133.512 ;
    END
  END src[352]
  PIN src[353]
    DIRECTION INPUT ;
    USE SIGNAL ;
    PORT
      LAYER M4 ;
        RECT  0 133.776 0.084 133.8 ;
    END
  END src[353]
  PIN src[354]
    DIRECTION INPUT ;
    USE SIGNAL ;
    PORT
      LAYER M4 ;
        RECT  0 134.064 0.084 134.088 ;
    END
  END src[354]
  PIN src[355]
    DIRECTION INPUT ;
    USE SIGNAL ;
    PORT
      LAYER M4 ;
        RECT  0 134.352 0.084 134.376 ;
    END
  END src[355]
  PIN src[356]
    DIRECTION INPUT ;
    USE SIGNAL ;
    PORT
      LAYER M4 ;
        RECT  0 134.64 0.084 134.664 ;
    END
  END src[356]
  PIN src[357]
    DIRECTION INPUT ;
    USE SIGNAL ;
    PORT
      LAYER M4 ;
        RECT  0 134.928 0.084 134.952 ;
    END
  END src[357]
  PIN src[358]
    DIRECTION INPUT ;
    USE SIGNAL ;
    PORT
      LAYER M4 ;
        RECT  0 135.216 0.084 135.24 ;
    END
  END src[358]
  PIN src[359]
    DIRECTION INPUT ;
    USE SIGNAL ;
    PORT
      LAYER M4 ;
        RECT  0 135.504 0.084 135.528 ;
    END
  END src[359]
  PIN src[35]
    DIRECTION INPUT ;
    USE SIGNAL ;
    PORT
      LAYER M4 ;
        RECT  0 42.192 0.084 42.216 ;
    END
  END src[35]
  PIN src[360]
    DIRECTION INPUT ;
    USE SIGNAL ;
    PORT
      LAYER M4 ;
        RECT  0 135.792 0.084 135.816 ;
    END
  END src[360]
  PIN src[361]
    DIRECTION INPUT ;
    USE SIGNAL ;
    PORT
      LAYER M4 ;
        RECT  0 136.08 0.084 136.104 ;
    END
  END src[361]
  PIN src[362]
    DIRECTION INPUT ;
    USE SIGNAL ;
    PORT
      LAYER M4 ;
        RECT  0 136.368 0.084 136.392 ;
    END
  END src[362]
  PIN src[363]
    DIRECTION INPUT ;
    USE SIGNAL ;
    PORT
      LAYER M4 ;
        RECT  0 136.656 0.084 136.68 ;
    END
  END src[363]
  PIN src[364]
    DIRECTION INPUT ;
    USE SIGNAL ;
    PORT
      LAYER M4 ;
        RECT  0 136.944 0.084 136.968 ;
    END
  END src[364]
  PIN src[365]
    DIRECTION INPUT ;
    USE SIGNAL ;
    PORT
      LAYER M4 ;
        RECT  0 137.232 0.084 137.256 ;
    END
  END src[365]
  PIN src[366]
    DIRECTION INPUT ;
    USE SIGNAL ;
    PORT
      LAYER M4 ;
        RECT  0 137.52 0.084 137.544 ;
    END
  END src[366]
  PIN src[367]
    DIRECTION INPUT ;
    USE SIGNAL ;
    PORT
      LAYER M4 ;
        RECT  0 137.808 0.084 137.832 ;
    END
  END src[367]
  PIN src[368]
    DIRECTION INPUT ;
    USE SIGNAL ;
    PORT
      LAYER M4 ;
        RECT  0 138.096 0.084 138.12 ;
    END
  END src[368]
  PIN src[369]
    DIRECTION INPUT ;
    USE SIGNAL ;
    PORT
      LAYER M4 ;
        RECT  0 138.384 0.084 138.408 ;
    END
  END src[369]
  PIN src[36]
    DIRECTION INPUT ;
    USE SIGNAL ;
    PORT
      LAYER M4 ;
        RECT  0 42.48 0.084 42.504 ;
    END
  END src[36]
  PIN src[370]
    DIRECTION INPUT ;
    USE SIGNAL ;
    PORT
      LAYER M4 ;
        RECT  0 138.672 0.084 138.696 ;
    END
  END src[370]
  PIN src[371]
    DIRECTION INPUT ;
    USE SIGNAL ;
    PORT
      LAYER M4 ;
        RECT  0 138.96 0.084 138.984 ;
    END
  END src[371]
  PIN src[372]
    DIRECTION INPUT ;
    USE SIGNAL ;
    PORT
      LAYER M4 ;
        RECT  0 139.248 0.084 139.272 ;
    END
  END src[372]
  PIN src[373]
    DIRECTION INPUT ;
    USE SIGNAL ;
    PORT
      LAYER M4 ;
        RECT  0 139.536 0.084 139.56 ;
    END
  END src[373]
  PIN src[374]
    DIRECTION INPUT ;
    USE SIGNAL ;
    PORT
      LAYER M4 ;
        RECT  0 139.824 0.084 139.848 ;
    END
  END src[374]
  PIN src[375]
    DIRECTION INPUT ;
    USE SIGNAL ;
    PORT
      LAYER M4 ;
        RECT  0 140.112 0.084 140.136 ;
    END
  END src[375]
  PIN src[376]
    DIRECTION INPUT ;
    USE SIGNAL ;
    PORT
      LAYER M4 ;
        RECT  0 140.4 0.084 140.424 ;
    END
  END src[376]
  PIN src[377]
    DIRECTION INPUT ;
    USE SIGNAL ;
    PORT
      LAYER M4 ;
        RECT  0 140.688 0.084 140.712 ;
    END
  END src[377]
  PIN src[378]
    DIRECTION INPUT ;
    USE SIGNAL ;
    PORT
      LAYER M4 ;
        RECT  0 140.976 0.084 141 ;
    END
  END src[378]
  PIN src[379]
    DIRECTION INPUT ;
    USE SIGNAL ;
    PORT
      LAYER M4 ;
        RECT  0 141.264 0.084 141.288 ;
    END
  END src[379]
  PIN src[37]
    DIRECTION INPUT ;
    USE SIGNAL ;
    PORT
      LAYER M4 ;
        RECT  0 42.768 0.084 42.792 ;
    END
  END src[37]
  PIN src[380]
    DIRECTION INPUT ;
    USE SIGNAL ;
    PORT
      LAYER M4 ;
        RECT  0 141.552 0.084 141.576 ;
    END
  END src[380]
  PIN src[381]
    DIRECTION INPUT ;
    USE SIGNAL ;
    PORT
      LAYER M4 ;
        RECT  0 141.84 0.084 141.864 ;
    END
  END src[381]
  PIN src[382]
    DIRECTION INPUT ;
    USE SIGNAL ;
    PORT
      LAYER M4 ;
        RECT  0 142.128 0.084 142.152 ;
    END
  END src[382]
  PIN src[383]
    DIRECTION INPUT ;
    USE SIGNAL ;
    PORT
      LAYER M4 ;
        RECT  0 142.416 0.084 142.44 ;
    END
  END src[383]
  PIN src[384]
    DIRECTION INPUT ;
    USE SIGNAL ;
    PORT
      LAYER M4 ;
        RECT  0 142.704 0.084 142.728 ;
    END
  END src[384]
  PIN src[385]
    DIRECTION INPUT ;
    USE SIGNAL ;
    PORT
      LAYER M4 ;
        RECT  0 142.992 0.084 143.016 ;
    END
  END src[385]
  PIN src[386]
    DIRECTION INPUT ;
    USE SIGNAL ;
    PORT
      LAYER M4 ;
        RECT  0 143.28 0.084 143.304 ;
    END
  END src[386]
  PIN src[387]
    DIRECTION INPUT ;
    USE SIGNAL ;
    PORT
      LAYER M4 ;
        RECT  0 143.568 0.084 143.592 ;
    END
  END src[387]
  PIN src[388]
    DIRECTION INPUT ;
    USE SIGNAL ;
    PORT
      LAYER M4 ;
        RECT  0 143.856 0.084 143.88 ;
    END
  END src[388]
  PIN src[389]
    DIRECTION INPUT ;
    USE SIGNAL ;
    PORT
      LAYER M4 ;
        RECT  0 144.144 0.084 144.168 ;
    END
  END src[389]
  PIN src[38]
    DIRECTION INPUT ;
    USE SIGNAL ;
    PORT
      LAYER M4 ;
        RECT  0 43.056 0.084 43.08 ;
    END
  END src[38]
  PIN src[390]
    DIRECTION INPUT ;
    USE SIGNAL ;
    PORT
      LAYER M4 ;
        RECT  0 144.432 0.084 144.456 ;
    END
  END src[390]
  PIN src[391]
    DIRECTION INPUT ;
    USE SIGNAL ;
    PORT
      LAYER M4 ;
        RECT  0 144.72 0.084 144.744 ;
    END
  END src[391]
  PIN src[392]
    DIRECTION INPUT ;
    USE SIGNAL ;
    PORT
      LAYER M4 ;
        RECT  0 145.008 0.084 145.032 ;
    END
  END src[392]
  PIN src[393]
    DIRECTION INPUT ;
    USE SIGNAL ;
    PORT
      LAYER M4 ;
        RECT  0 145.296 0.084 145.32 ;
    END
  END src[393]
  PIN src[394]
    DIRECTION INPUT ;
    USE SIGNAL ;
    PORT
      LAYER M4 ;
        RECT  0 145.584 0.084 145.608 ;
    END
  END src[394]
  PIN src[395]
    DIRECTION INPUT ;
    USE SIGNAL ;
    PORT
      LAYER M4 ;
        RECT  0 145.872 0.084 145.896 ;
    END
  END src[395]
  PIN src[396]
    DIRECTION INPUT ;
    USE SIGNAL ;
    PORT
      LAYER M4 ;
        RECT  0 146.16 0.084 146.184 ;
    END
  END src[396]
  PIN src[397]
    DIRECTION INPUT ;
    USE SIGNAL ;
    PORT
      LAYER M4 ;
        RECT  0 146.448 0.084 146.472 ;
    END
  END src[397]
  PIN src[398]
    DIRECTION INPUT ;
    USE SIGNAL ;
    PORT
      LAYER M4 ;
        RECT  0 146.736 0.084 146.76 ;
    END
  END src[398]
  PIN src[399]
    DIRECTION INPUT ;
    USE SIGNAL ;
    PORT
      LAYER M4 ;
        RECT  0 147.024 0.084 147.048 ;
    END
  END src[399]
  PIN src[39]
    DIRECTION INPUT ;
    USE SIGNAL ;
    PORT
      LAYER M4 ;
        RECT  0 43.344 0.084 43.368 ;
    END
  END src[39]
  PIN src[3]
    DIRECTION INPUT ;
    USE SIGNAL ;
    PORT
      LAYER M4 ;
        RECT  0 32.976 0.084 33 ;
    END
  END src[3]
  PIN src[400]
    DIRECTION INPUT ;
    USE SIGNAL ;
    PORT
      LAYER M4 ;
        RECT  0 147.312 0.084 147.336 ;
    END
  END src[400]
  PIN src[401]
    DIRECTION INPUT ;
    USE SIGNAL ;
    PORT
      LAYER M4 ;
        RECT  0 147.6 0.084 147.624 ;
    END
  END src[401]
  PIN src[402]
    DIRECTION INPUT ;
    USE SIGNAL ;
    PORT
      LAYER M4 ;
        RECT  0 147.888 0.084 147.912 ;
    END
  END src[402]
  PIN src[403]
    DIRECTION INPUT ;
    USE SIGNAL ;
    PORT
      LAYER M4 ;
        RECT  0 148.176 0.084 148.2 ;
    END
  END src[403]
  PIN src[404]
    DIRECTION INPUT ;
    USE SIGNAL ;
    PORT
      LAYER M4 ;
        RECT  0 148.464 0.084 148.488 ;
    END
  END src[404]
  PIN src[405]
    DIRECTION INPUT ;
    USE SIGNAL ;
    PORT
      LAYER M4 ;
        RECT  0 148.752 0.084 148.776 ;
    END
  END src[405]
  PIN src[406]
    DIRECTION INPUT ;
    USE SIGNAL ;
    PORT
      LAYER M4 ;
        RECT  0 149.04 0.084 149.064 ;
    END
  END src[406]
  PIN src[407]
    DIRECTION INPUT ;
    USE SIGNAL ;
    PORT
      LAYER M4 ;
        RECT  0 149.328 0.084 149.352 ;
    END
  END src[407]
  PIN src[408]
    DIRECTION INPUT ;
    USE SIGNAL ;
    PORT
      LAYER M4 ;
        RECT  0 149.616 0.084 149.64 ;
    END
  END src[408]
  PIN src[409]
    DIRECTION INPUT ;
    USE SIGNAL ;
    PORT
      LAYER M4 ;
        RECT  0 149.904 0.084 149.928 ;
    END
  END src[409]
  PIN src[40]
    DIRECTION INPUT ;
    USE SIGNAL ;
    PORT
      LAYER M4 ;
        RECT  0 43.632 0.084 43.656 ;
    END
  END src[40]
  PIN src[410]
    DIRECTION INPUT ;
    USE SIGNAL ;
    PORT
      LAYER M4 ;
        RECT  0 150.192 0.084 150.216 ;
    END
  END src[410]
  PIN src[411]
    DIRECTION INPUT ;
    USE SIGNAL ;
    PORT
      LAYER M4 ;
        RECT  0 150.48 0.084 150.504 ;
    END
  END src[411]
  PIN src[412]
    DIRECTION INPUT ;
    USE SIGNAL ;
    PORT
      LAYER M4 ;
        RECT  0 150.768 0.084 150.792 ;
    END
  END src[412]
  PIN src[413]
    DIRECTION INPUT ;
    USE SIGNAL ;
    PORT
      LAYER M4 ;
        RECT  0 151.056 0.084 151.08 ;
    END
  END src[413]
  PIN src[414]
    DIRECTION INPUT ;
    USE SIGNAL ;
    PORT
      LAYER M4 ;
        RECT  0 151.344 0.084 151.368 ;
    END
  END src[414]
  PIN src[415]
    DIRECTION INPUT ;
    USE SIGNAL ;
    PORT
      LAYER M4 ;
        RECT  0 151.632 0.084 151.656 ;
    END
  END src[415]
  PIN src[416]
    DIRECTION INPUT ;
    USE SIGNAL ;
    PORT
      LAYER M4 ;
        RECT  0 151.92 0.084 151.944 ;
    END
  END src[416]
  PIN src[417]
    DIRECTION INPUT ;
    USE SIGNAL ;
    PORT
      LAYER M4 ;
        RECT  0 152.208 0.084 152.232 ;
    END
  END src[417]
  PIN src[418]
    DIRECTION INPUT ;
    USE SIGNAL ;
    PORT
      LAYER M4 ;
        RECT  0 152.496 0.084 152.52 ;
    END
  END src[418]
  PIN src[419]
    DIRECTION INPUT ;
    USE SIGNAL ;
    PORT
      LAYER M4 ;
        RECT  0 152.784 0.084 152.808 ;
    END
  END src[419]
  PIN src[41]
    DIRECTION INPUT ;
    USE SIGNAL ;
    PORT
      LAYER M4 ;
        RECT  0 43.92 0.084 43.944 ;
    END
  END src[41]
  PIN src[420]
    DIRECTION INPUT ;
    USE SIGNAL ;
    PORT
      LAYER M4 ;
        RECT  0 153.072 0.084 153.096 ;
    END
  END src[420]
  PIN src[421]
    DIRECTION INPUT ;
    USE SIGNAL ;
    PORT
      LAYER M4 ;
        RECT  0 153.36 0.084 153.384 ;
    END
  END src[421]
  PIN src[422]
    DIRECTION INPUT ;
    USE SIGNAL ;
    PORT
      LAYER M4 ;
        RECT  0 153.648 0.084 153.672 ;
    END
  END src[422]
  PIN src[423]
    DIRECTION INPUT ;
    USE SIGNAL ;
    PORT
      LAYER M4 ;
        RECT  0 153.936 0.084 153.96 ;
    END
  END src[423]
  PIN src[424]
    DIRECTION INPUT ;
    USE SIGNAL ;
    PORT
      LAYER M4 ;
        RECT  0 154.224 0.084 154.248 ;
    END
  END src[424]
  PIN src[425]
    DIRECTION INPUT ;
    USE SIGNAL ;
    PORT
      LAYER M4 ;
        RECT  0 154.512 0.084 154.536 ;
    END
  END src[425]
  PIN src[426]
    DIRECTION INPUT ;
    USE SIGNAL ;
    PORT
      LAYER M4 ;
        RECT  0 154.8 0.084 154.824 ;
    END
  END src[426]
  PIN src[427]
    DIRECTION INPUT ;
    USE SIGNAL ;
    PORT
      LAYER M4 ;
        RECT  0 155.088 0.084 155.112 ;
    END
  END src[427]
  PIN src[428]
    DIRECTION INPUT ;
    USE SIGNAL ;
    PORT
      LAYER M4 ;
        RECT  0 155.376 0.084 155.4 ;
    END
  END src[428]
  PIN src[429]
    DIRECTION INPUT ;
    USE SIGNAL ;
    PORT
      LAYER M4 ;
        RECT  0 155.664 0.084 155.688 ;
    END
  END src[429]
  PIN src[42]
    DIRECTION INPUT ;
    USE SIGNAL ;
    PORT
      LAYER M4 ;
        RECT  0 44.208 0.084 44.232 ;
    END
  END src[42]
  PIN src[430]
    DIRECTION INPUT ;
    USE SIGNAL ;
    PORT
      LAYER M4 ;
        RECT  0 155.952 0.084 155.976 ;
    END
  END src[430]
  PIN src[431]
    DIRECTION INPUT ;
    USE SIGNAL ;
    PORT
      LAYER M4 ;
        RECT  0 156.24 0.084 156.264 ;
    END
  END src[431]
  PIN src[432]
    DIRECTION INPUT ;
    USE SIGNAL ;
    PORT
      LAYER M4 ;
        RECT  0 156.528 0.084 156.552 ;
    END
  END src[432]
  PIN src[433]
    DIRECTION INPUT ;
    USE SIGNAL ;
    PORT
      LAYER M4 ;
        RECT  0 156.816 0.084 156.84 ;
    END
  END src[433]
  PIN src[434]
    DIRECTION INPUT ;
    USE SIGNAL ;
    PORT
      LAYER M4 ;
        RECT  0 157.104 0.084 157.128 ;
    END
  END src[434]
  PIN src[435]
    DIRECTION INPUT ;
    USE SIGNAL ;
    PORT
      LAYER M4 ;
        RECT  0 157.392 0.084 157.416 ;
    END
  END src[435]
  PIN src[436]
    DIRECTION INPUT ;
    USE SIGNAL ;
    PORT
      LAYER M4 ;
        RECT  0 157.68 0.084 157.704 ;
    END
  END src[436]
  PIN src[437]
    DIRECTION INPUT ;
    USE SIGNAL ;
    PORT
      LAYER M4 ;
        RECT  0 157.968 0.084 157.992 ;
    END
  END src[437]
  PIN src[438]
    DIRECTION INPUT ;
    USE SIGNAL ;
    PORT
      LAYER M4 ;
        RECT  0 158.256 0.084 158.28 ;
    END
  END src[438]
  PIN src[439]
    DIRECTION INPUT ;
    USE SIGNAL ;
    PORT
      LAYER M4 ;
        RECT  0 158.544 0.084 158.568 ;
    END
  END src[439]
  PIN src[43]
    DIRECTION INPUT ;
    USE SIGNAL ;
    PORT
      LAYER M4 ;
        RECT  0 44.496 0.084 44.52 ;
    END
  END src[43]
  PIN src[440]
    DIRECTION INPUT ;
    USE SIGNAL ;
    PORT
      LAYER M4 ;
        RECT  0 158.832 0.084 158.856 ;
    END
  END src[440]
  PIN src[441]
    DIRECTION INPUT ;
    USE SIGNAL ;
    PORT
      LAYER M4 ;
        RECT  0 159.12 0.084 159.144 ;
    END
  END src[441]
  PIN src[442]
    DIRECTION INPUT ;
    USE SIGNAL ;
    PORT
      LAYER M4 ;
        RECT  0 159.408 0.084 159.432 ;
    END
  END src[442]
  PIN src[443]
    DIRECTION INPUT ;
    USE SIGNAL ;
    PORT
      LAYER M4 ;
        RECT  0 159.696 0.084 159.72 ;
    END
  END src[443]
  PIN src[444]
    DIRECTION INPUT ;
    USE SIGNAL ;
    PORT
      LAYER M4 ;
        RECT  0 159.984 0.084 160.008 ;
    END
  END src[444]
  PIN src[445]
    DIRECTION INPUT ;
    USE SIGNAL ;
    PORT
      LAYER M4 ;
        RECT  0 160.272 0.084 160.296 ;
    END
  END src[445]
  PIN src[446]
    DIRECTION INPUT ;
    USE SIGNAL ;
    PORT
      LAYER M4 ;
        RECT  0 160.56 0.084 160.584 ;
    END
  END src[446]
  PIN src[447]
    DIRECTION INPUT ;
    USE SIGNAL ;
    PORT
      LAYER M4 ;
        RECT  0 160.848 0.084 160.872 ;
    END
  END src[447]
  PIN src[448]
    DIRECTION INPUT ;
    USE SIGNAL ;
    PORT
      LAYER M4 ;
        RECT  0 161.136 0.084 161.16 ;
    END
  END src[448]
  PIN src[449]
    DIRECTION INPUT ;
    USE SIGNAL ;
    PORT
      LAYER M4 ;
        RECT  0 161.424 0.084 161.448 ;
    END
  END src[449]
  PIN src[44]
    DIRECTION INPUT ;
    USE SIGNAL ;
    PORT
      LAYER M4 ;
        RECT  0 44.784 0.084 44.808 ;
    END
  END src[44]
  PIN src[450]
    DIRECTION INPUT ;
    USE SIGNAL ;
    PORT
      LAYER M4 ;
        RECT  0 161.712 0.084 161.736 ;
    END
  END src[450]
  PIN src[451]
    DIRECTION INPUT ;
    USE SIGNAL ;
    PORT
      LAYER M4 ;
        RECT  0 162 0.084 162.024 ;
    END
  END src[451]
  PIN src[452]
    DIRECTION INPUT ;
    USE SIGNAL ;
    PORT
      LAYER M4 ;
        RECT  0 162.288 0.084 162.312 ;
    END
  END src[452]
  PIN src[453]
    DIRECTION INPUT ;
    USE SIGNAL ;
    PORT
      LAYER M4 ;
        RECT  0 162.576 0.084 162.6 ;
    END
  END src[453]
  PIN src[454]
    DIRECTION INPUT ;
    USE SIGNAL ;
    PORT
      LAYER M4 ;
        RECT  0 162.864 0.084 162.888 ;
    END
  END src[454]
  PIN src[455]
    DIRECTION INPUT ;
    USE SIGNAL ;
    PORT
      LAYER M4 ;
        RECT  0 163.152 0.084 163.176 ;
    END
  END src[455]
  PIN src[456]
    DIRECTION INPUT ;
    USE SIGNAL ;
    PORT
      LAYER M4 ;
        RECT  0 163.44 0.084 163.464 ;
    END
  END src[456]
  PIN src[457]
    DIRECTION INPUT ;
    USE SIGNAL ;
    PORT
      LAYER M4 ;
        RECT  0 163.728 0.084 163.752 ;
    END
  END src[457]
  PIN src[458]
    DIRECTION INPUT ;
    USE SIGNAL ;
    PORT
      LAYER M4 ;
        RECT  0 164.016 0.084 164.04 ;
    END
  END src[458]
  PIN src[459]
    DIRECTION INPUT ;
    USE SIGNAL ;
    PORT
      LAYER M4 ;
        RECT  0 164.304 0.084 164.328 ;
    END
  END src[459]
  PIN src[45]
    DIRECTION INPUT ;
    USE SIGNAL ;
    PORT
      LAYER M4 ;
        RECT  0 45.072 0.084 45.096 ;
    END
  END src[45]
  PIN src[460]
    DIRECTION INPUT ;
    USE SIGNAL ;
    PORT
      LAYER M4 ;
        RECT  0 164.592 0.084 164.616 ;
    END
  END src[460]
  PIN src[461]
    DIRECTION INPUT ;
    USE SIGNAL ;
    PORT
      LAYER M4 ;
        RECT  0 164.88 0.084 164.904 ;
    END
  END src[461]
  PIN src[462]
    DIRECTION INPUT ;
    USE SIGNAL ;
    PORT
      LAYER M4 ;
        RECT  0 165.168 0.084 165.192 ;
    END
  END src[462]
  PIN src[463]
    DIRECTION INPUT ;
    USE SIGNAL ;
    PORT
      LAYER M4 ;
        RECT  0 165.456 0.084 165.48 ;
    END
  END src[463]
  PIN src[464]
    DIRECTION INPUT ;
    USE SIGNAL ;
    PORT
      LAYER M4 ;
        RECT  0 165.744 0.084 165.768 ;
    END
  END src[464]
  PIN src[465]
    DIRECTION INPUT ;
    USE SIGNAL ;
    PORT
      LAYER M4 ;
        RECT  0 166.032 0.084 166.056 ;
    END
  END src[465]
  PIN src[466]
    DIRECTION INPUT ;
    USE SIGNAL ;
    PORT
      LAYER M4 ;
        RECT  0 166.32 0.084 166.344 ;
    END
  END src[466]
  PIN src[467]
    DIRECTION INPUT ;
    USE SIGNAL ;
    PORT
      LAYER M4 ;
        RECT  0 166.608 0.084 166.632 ;
    END
  END src[467]
  PIN src[468]
    DIRECTION INPUT ;
    USE SIGNAL ;
    PORT
      LAYER M4 ;
        RECT  0 166.896 0.084 166.92 ;
    END
  END src[468]
  PIN src[469]
    DIRECTION INPUT ;
    USE SIGNAL ;
    PORT
      LAYER M4 ;
        RECT  0 167.184 0.084 167.208 ;
    END
  END src[469]
  PIN src[46]
    DIRECTION INPUT ;
    USE SIGNAL ;
    PORT
      LAYER M4 ;
        RECT  0 45.36 0.084 45.384 ;
    END
  END src[46]
  PIN src[470]
    DIRECTION INPUT ;
    USE SIGNAL ;
    PORT
      LAYER M4 ;
        RECT  0 167.472 0.084 167.496 ;
    END
  END src[470]
  PIN src[471]
    DIRECTION INPUT ;
    USE SIGNAL ;
    PORT
      LAYER M4 ;
        RECT  0 167.76 0.084 167.784 ;
    END
  END src[471]
  PIN src[472]
    DIRECTION INPUT ;
    USE SIGNAL ;
    PORT
      LAYER M4 ;
        RECT  0 168.048 0.084 168.072 ;
    END
  END src[472]
  PIN src[473]
    DIRECTION INPUT ;
    USE SIGNAL ;
    PORT
      LAYER M4 ;
        RECT  0 168.336 0.084 168.36 ;
    END
  END src[473]
  PIN src[474]
    DIRECTION INPUT ;
    USE SIGNAL ;
    PORT
      LAYER M4 ;
        RECT  0 168.624 0.084 168.648 ;
    END
  END src[474]
  PIN src[475]
    DIRECTION INPUT ;
    USE SIGNAL ;
    PORT
      LAYER M4 ;
        RECT  0 168.912 0.084 168.936 ;
    END
  END src[475]
  PIN src[476]
    DIRECTION INPUT ;
    USE SIGNAL ;
    PORT
      LAYER M4 ;
        RECT  0 169.2 0.084 169.224 ;
    END
  END src[476]
  PIN src[477]
    DIRECTION INPUT ;
    USE SIGNAL ;
    PORT
      LAYER M4 ;
        RECT  0 169.488 0.084 169.512 ;
    END
  END src[477]
  PIN src[478]
    DIRECTION INPUT ;
    USE SIGNAL ;
    PORT
      LAYER M4 ;
        RECT  0 169.776 0.084 169.8 ;
    END
  END src[478]
  PIN src[479]
    DIRECTION INPUT ;
    USE SIGNAL ;
    PORT
      LAYER M4 ;
        RECT  0 170.064 0.084 170.088 ;
    END
  END src[479]
  PIN src[47]
    DIRECTION INPUT ;
    USE SIGNAL ;
    PORT
      LAYER M4 ;
        RECT  0 45.648 0.084 45.672 ;
    END
  END src[47]
  PIN src[480]
    DIRECTION INPUT ;
    USE SIGNAL ;
    PORT
      LAYER M4 ;
        RECT  0 170.352 0.084 170.376 ;
    END
  END src[480]
  PIN src[481]
    DIRECTION INPUT ;
    USE SIGNAL ;
    PORT
      LAYER M4 ;
        RECT  0 170.64 0.084 170.664 ;
    END
  END src[481]
  PIN src[482]
    DIRECTION INPUT ;
    USE SIGNAL ;
    PORT
      LAYER M4 ;
        RECT  0 170.928 0.084 170.952 ;
    END
  END src[482]
  PIN src[483]
    DIRECTION INPUT ;
    USE SIGNAL ;
    PORT
      LAYER M4 ;
        RECT  0 171.216 0.084 171.24 ;
    END
  END src[483]
  PIN src[484]
    DIRECTION INPUT ;
    USE SIGNAL ;
    PORT
      LAYER M4 ;
        RECT  0 171.504 0.084 171.528 ;
    END
  END src[484]
  PIN src[485]
    DIRECTION INPUT ;
    USE SIGNAL ;
    PORT
      LAYER M4 ;
        RECT  0 171.792 0.084 171.816 ;
    END
  END src[485]
  PIN src[486]
    DIRECTION INPUT ;
    USE SIGNAL ;
    PORT
      LAYER M4 ;
        RECT  0 172.08 0.084 172.104 ;
    END
  END src[486]
  PIN src[487]
    DIRECTION INPUT ;
    USE SIGNAL ;
    PORT
      LAYER M4 ;
        RECT  0 172.368 0.084 172.392 ;
    END
  END src[487]
  PIN src[488]
    DIRECTION INPUT ;
    USE SIGNAL ;
    PORT
      LAYER M4 ;
        RECT  0 172.656 0.084 172.68 ;
    END
  END src[488]
  PIN src[489]
    DIRECTION INPUT ;
    USE SIGNAL ;
    PORT
      LAYER M4 ;
        RECT  0 172.944 0.084 172.968 ;
    END
  END src[489]
  PIN src[48]
    DIRECTION INPUT ;
    USE SIGNAL ;
    PORT
      LAYER M4 ;
        RECT  0 45.936 0.084 45.96 ;
    END
  END src[48]
  PIN src[490]
    DIRECTION INPUT ;
    USE SIGNAL ;
    PORT
      LAYER M4 ;
        RECT  0 173.232 0.084 173.256 ;
    END
  END src[490]
  PIN src[491]
    DIRECTION INPUT ;
    USE SIGNAL ;
    PORT
      LAYER M4 ;
        RECT  0 173.52 0.084 173.544 ;
    END
  END src[491]
  PIN src[492]
    DIRECTION INPUT ;
    USE SIGNAL ;
    PORT
      LAYER M4 ;
        RECT  0 173.808 0.084 173.832 ;
    END
  END src[492]
  PIN src[493]
    DIRECTION INPUT ;
    USE SIGNAL ;
    PORT
      LAYER M4 ;
        RECT  0 174.096 0.084 174.12 ;
    END
  END src[493]
  PIN src[494]
    DIRECTION INPUT ;
    USE SIGNAL ;
    PORT
      LAYER M4 ;
        RECT  0 174.384 0.084 174.408 ;
    END
  END src[494]
  PIN src[495]
    DIRECTION INPUT ;
    USE SIGNAL ;
    PORT
      LAYER M4 ;
        RECT  0 174.672 0.084 174.696 ;
    END
  END src[495]
  PIN src[496]
    DIRECTION INPUT ;
    USE SIGNAL ;
    PORT
      LAYER M4 ;
        RECT  0 174.96 0.084 174.984 ;
    END
  END src[496]
  PIN src[497]
    DIRECTION INPUT ;
    USE SIGNAL ;
    PORT
      LAYER M4 ;
        RECT  0 175.248 0.084 175.272 ;
    END
  END src[497]
  PIN src[498]
    DIRECTION INPUT ;
    USE SIGNAL ;
    PORT
      LAYER M4 ;
        RECT  0 175.536 0.084 175.56 ;
    END
  END src[498]
  PIN src[499]
    DIRECTION INPUT ;
    USE SIGNAL ;
    PORT
      LAYER M4 ;
        RECT  0 175.824 0.084 175.848 ;
    END
  END src[499]
  PIN src[49]
    DIRECTION INPUT ;
    USE SIGNAL ;
    PORT
      LAYER M4 ;
        RECT  0 46.224 0.084 46.248 ;
    END
  END src[49]
  PIN src[4]
    DIRECTION INPUT ;
    USE SIGNAL ;
    PORT
      LAYER M4 ;
        RECT  0 33.264 0.084 33.288 ;
    END
  END src[4]
  PIN src[500]
    DIRECTION INPUT ;
    USE SIGNAL ;
    PORT
      LAYER M4 ;
        RECT  0 176.112 0.084 176.136 ;
    END
  END src[500]
  PIN src[501]
    DIRECTION INPUT ;
    USE SIGNAL ;
    PORT
      LAYER M4 ;
        RECT  0 176.4 0.084 176.424 ;
    END
  END src[501]
  PIN src[502]
    DIRECTION INPUT ;
    USE SIGNAL ;
    PORT
      LAYER M4 ;
        RECT  0 176.688 0.084 176.712 ;
    END
  END src[502]
  PIN src[503]
    DIRECTION INPUT ;
    USE SIGNAL ;
    PORT
      LAYER M4 ;
        RECT  0 176.976 0.084 177 ;
    END
  END src[503]
  PIN src[504]
    DIRECTION INPUT ;
    USE SIGNAL ;
    PORT
      LAYER M4 ;
        RECT  0 177.264 0.084 177.288 ;
    END
  END src[504]
  PIN src[505]
    DIRECTION INPUT ;
    USE SIGNAL ;
    PORT
      LAYER M4 ;
        RECT  0 177.552 0.084 177.576 ;
    END
  END src[505]
  PIN src[506]
    DIRECTION INPUT ;
    USE SIGNAL ;
    PORT
      LAYER M4 ;
        RECT  0 177.84 0.084 177.864 ;
    END
  END src[506]
  PIN src[507]
    DIRECTION INPUT ;
    USE SIGNAL ;
    PORT
      LAYER M4 ;
        RECT  0 178.128 0.084 178.152 ;
    END
  END src[507]
  PIN src[508]
    DIRECTION INPUT ;
    USE SIGNAL ;
    PORT
      LAYER M4 ;
        RECT  0 178.416 0.084 178.44 ;
    END
  END src[508]
  PIN src[509]
    DIRECTION INPUT ;
    USE SIGNAL ;
    PORT
      LAYER M4 ;
        RECT  0 178.704 0.084 178.728 ;
    END
  END src[509]
  PIN src[50]
    DIRECTION INPUT ;
    USE SIGNAL ;
    PORT
      LAYER M4 ;
        RECT  0 46.512 0.084 46.536 ;
    END
  END src[50]
  PIN src[510]
    DIRECTION INPUT ;
    USE SIGNAL ;
    PORT
      LAYER M4 ;
        RECT  0 178.992 0.084 179.016 ;
    END
  END src[510]
  PIN src[511]
    DIRECTION INPUT ;
    USE SIGNAL ;
    PORT
      LAYER M4 ;
        RECT  0 179.28 0.084 179.304 ;
    END
  END src[511]
  PIN src[51]
    DIRECTION INPUT ;
    USE SIGNAL ;
    PORT
      LAYER M4 ;
        RECT  0 46.8 0.084 46.824 ;
    END
  END src[51]
  PIN src[52]
    DIRECTION INPUT ;
    USE SIGNAL ;
    PORT
      LAYER M4 ;
        RECT  0 47.088 0.084 47.112 ;
    END
  END src[52]
  PIN src[53]
    DIRECTION INPUT ;
    USE SIGNAL ;
    PORT
      LAYER M4 ;
        RECT  0 47.376 0.084 47.4 ;
    END
  END src[53]
  PIN src[54]
    DIRECTION INPUT ;
    USE SIGNAL ;
    PORT
      LAYER M4 ;
        RECT  0 47.664 0.084 47.688 ;
    END
  END src[54]
  PIN src[55]
    DIRECTION INPUT ;
    USE SIGNAL ;
    PORT
      LAYER M4 ;
        RECT  0 47.952 0.084 47.976 ;
    END
  END src[55]
  PIN src[56]
    DIRECTION INPUT ;
    USE SIGNAL ;
    PORT
      LAYER M4 ;
        RECT  0 48.24 0.084 48.264 ;
    END
  END src[56]
  PIN src[57]
    DIRECTION INPUT ;
    USE SIGNAL ;
    PORT
      LAYER M4 ;
        RECT  0 48.528 0.084 48.552 ;
    END
  END src[57]
  PIN src[58]
    DIRECTION INPUT ;
    USE SIGNAL ;
    PORT
      LAYER M4 ;
        RECT  0 48.816 0.084 48.84 ;
    END
  END src[58]
  PIN src[59]
    DIRECTION INPUT ;
    USE SIGNAL ;
    PORT
      LAYER M4 ;
        RECT  0 49.104 0.084 49.128 ;
    END
  END src[59]
  PIN src[5]
    DIRECTION INPUT ;
    USE SIGNAL ;
    PORT
      LAYER M4 ;
        RECT  0 33.552 0.084 33.576 ;
    END
  END src[5]
  PIN src[60]
    DIRECTION INPUT ;
    USE SIGNAL ;
    PORT
      LAYER M4 ;
        RECT  0 49.392 0.084 49.416 ;
    END
  END src[60]
  PIN src[61]
    DIRECTION INPUT ;
    USE SIGNAL ;
    PORT
      LAYER M4 ;
        RECT  0 49.68 0.084 49.704 ;
    END
  END src[61]
  PIN src[62]
    DIRECTION INPUT ;
    USE SIGNAL ;
    PORT
      LAYER M4 ;
        RECT  0 49.968 0.084 49.992 ;
    END
  END src[62]
  PIN src[63]
    DIRECTION INPUT ;
    USE SIGNAL ;
    PORT
      LAYER M4 ;
        RECT  0 50.256 0.084 50.28 ;
    END
  END src[63]
  PIN src[64]
    DIRECTION INPUT ;
    USE SIGNAL ;
    PORT
      LAYER M4 ;
        RECT  0 50.544 0.084 50.568 ;
    END
  END src[64]
  PIN src[65]
    DIRECTION INPUT ;
    USE SIGNAL ;
    PORT
      LAYER M4 ;
        RECT  0 50.832 0.084 50.856 ;
    END
  END src[65]
  PIN src[66]
    DIRECTION INPUT ;
    USE SIGNAL ;
    PORT
      LAYER M4 ;
        RECT  0 51.12 0.084 51.144 ;
    END
  END src[66]
  PIN src[67]
    DIRECTION INPUT ;
    USE SIGNAL ;
    PORT
      LAYER M4 ;
        RECT  0 51.408 0.084 51.432 ;
    END
  END src[67]
  PIN src[68]
    DIRECTION INPUT ;
    USE SIGNAL ;
    PORT
      LAYER M4 ;
        RECT  0 51.696 0.084 51.72 ;
    END
  END src[68]
  PIN src[69]
    DIRECTION INPUT ;
    USE SIGNAL ;
    PORT
      LAYER M4 ;
        RECT  0 51.984 0.084 52.008 ;
    END
  END src[69]
  PIN src[6]
    DIRECTION INPUT ;
    USE SIGNAL ;
    PORT
      LAYER M4 ;
        RECT  0 33.84 0.084 33.864 ;
    END
  END src[6]
  PIN src[70]
    DIRECTION INPUT ;
    USE SIGNAL ;
    PORT
      LAYER M4 ;
        RECT  0 52.272 0.084 52.296 ;
    END
  END src[70]
  PIN src[71]
    DIRECTION INPUT ;
    USE SIGNAL ;
    PORT
      LAYER M4 ;
        RECT  0 52.56 0.084 52.584 ;
    END
  END src[71]
  PIN src[72]
    DIRECTION INPUT ;
    USE SIGNAL ;
    PORT
      LAYER M4 ;
        RECT  0 52.848 0.084 52.872 ;
    END
  END src[72]
  PIN src[73]
    DIRECTION INPUT ;
    USE SIGNAL ;
    PORT
      LAYER M4 ;
        RECT  0 53.136 0.084 53.16 ;
    END
  END src[73]
  PIN src[74]
    DIRECTION INPUT ;
    USE SIGNAL ;
    PORT
      LAYER M4 ;
        RECT  0 53.424 0.084 53.448 ;
    END
  END src[74]
  PIN src[75]
    DIRECTION INPUT ;
    USE SIGNAL ;
    PORT
      LAYER M4 ;
        RECT  0 53.712 0.084 53.736 ;
    END
  END src[75]
  PIN src[76]
    DIRECTION INPUT ;
    USE SIGNAL ;
    PORT
      LAYER M4 ;
        RECT  0 54 0.084 54.024 ;
    END
  END src[76]
  PIN src[77]
    DIRECTION INPUT ;
    USE SIGNAL ;
    PORT
      LAYER M4 ;
        RECT  0 54.288 0.084 54.312 ;
    END
  END src[77]
  PIN src[78]
    DIRECTION INPUT ;
    USE SIGNAL ;
    PORT
      LAYER M4 ;
        RECT  0 54.576 0.084 54.6 ;
    END
  END src[78]
  PIN src[79]
    DIRECTION INPUT ;
    USE SIGNAL ;
    PORT
      LAYER M4 ;
        RECT  0 54.864 0.084 54.888 ;
    END
  END src[79]
  PIN src[7]
    DIRECTION INPUT ;
    USE SIGNAL ;
    PORT
      LAYER M4 ;
        RECT  0 34.128 0.084 34.152 ;
    END
  END src[7]
  PIN src[80]
    DIRECTION INPUT ;
    USE SIGNAL ;
    PORT
      LAYER M4 ;
        RECT  0 55.152 0.084 55.176 ;
    END
  END src[80]
  PIN src[81]
    DIRECTION INPUT ;
    USE SIGNAL ;
    PORT
      LAYER M4 ;
        RECT  0 55.44 0.084 55.464 ;
    END
  END src[81]
  PIN src[82]
    DIRECTION INPUT ;
    USE SIGNAL ;
    PORT
      LAYER M4 ;
        RECT  0 55.728 0.084 55.752 ;
    END
  END src[82]
  PIN src[83]
    DIRECTION INPUT ;
    USE SIGNAL ;
    PORT
      LAYER M4 ;
        RECT  0 56.016 0.084 56.04 ;
    END
  END src[83]
  PIN src[84]
    DIRECTION INPUT ;
    USE SIGNAL ;
    PORT
      LAYER M4 ;
        RECT  0 56.304 0.084 56.328 ;
    END
  END src[84]
  PIN src[85]
    DIRECTION INPUT ;
    USE SIGNAL ;
    PORT
      LAYER M4 ;
        RECT  0 56.592 0.084 56.616 ;
    END
  END src[85]
  PIN src[86]
    DIRECTION INPUT ;
    USE SIGNAL ;
    PORT
      LAYER M4 ;
        RECT  0 56.88 0.084 56.904 ;
    END
  END src[86]
  PIN src[87]
    DIRECTION INPUT ;
    USE SIGNAL ;
    PORT
      LAYER M4 ;
        RECT  0 57.168 0.084 57.192 ;
    END
  END src[87]
  PIN src[88]
    DIRECTION INPUT ;
    USE SIGNAL ;
    PORT
      LAYER M4 ;
        RECT  0 57.456 0.084 57.48 ;
    END
  END src[88]
  PIN src[89]
    DIRECTION INPUT ;
    USE SIGNAL ;
    PORT
      LAYER M4 ;
        RECT  0 57.744 0.084 57.768 ;
    END
  END src[89]
  PIN src[8]
    DIRECTION INPUT ;
    USE SIGNAL ;
    PORT
      LAYER M4 ;
        RECT  0 34.416 0.084 34.44 ;
    END
  END src[8]
  PIN src[90]
    DIRECTION INPUT ;
    USE SIGNAL ;
    PORT
      LAYER M4 ;
        RECT  0 58.032 0.084 58.056 ;
    END
  END src[90]
  PIN src[91]
    DIRECTION INPUT ;
    USE SIGNAL ;
    PORT
      LAYER M4 ;
        RECT  0 58.32 0.084 58.344 ;
    END
  END src[91]
  PIN src[92]
    DIRECTION INPUT ;
    USE SIGNAL ;
    PORT
      LAYER M4 ;
        RECT  0 58.608 0.084 58.632 ;
    END
  END src[92]
  PIN src[93]
    DIRECTION INPUT ;
    USE SIGNAL ;
    PORT
      LAYER M4 ;
        RECT  0 58.896 0.084 58.92 ;
    END
  END src[93]
  PIN src[94]
    DIRECTION INPUT ;
    USE SIGNAL ;
    PORT
      LAYER M4 ;
        RECT  0 59.184 0.084 59.208 ;
    END
  END src[94]
  PIN src[95]
    DIRECTION INPUT ;
    USE SIGNAL ;
    PORT
      LAYER M4 ;
        RECT  0 59.472 0.084 59.496 ;
    END
  END src[95]
  PIN src[96]
    DIRECTION INPUT ;
    USE SIGNAL ;
    PORT
      LAYER M4 ;
        RECT  0 59.76 0.084 59.784 ;
    END
  END src[96]
  PIN src[97]
    DIRECTION INPUT ;
    USE SIGNAL ;
    PORT
      LAYER M4 ;
        RECT  0 60.048 0.084 60.072 ;
    END
  END src[97]
  PIN src[98]
    DIRECTION INPUT ;
    USE SIGNAL ;
    PORT
      LAYER M4 ;
        RECT  0 60.336 0.084 60.36 ;
    END
  END src[98]
  PIN src[99]
    DIRECTION INPUT ;
    USE SIGNAL ;
    PORT
      LAYER M4 ;
        RECT  0 60.624 0.084 60.648 ;
    END
  END src[99]
  PIN src[9]
    DIRECTION INPUT ;
    USE SIGNAL ;
    PORT
      LAYER M4 ;
        RECT  0 34.704 0.084 34.728 ;
    END
  END src[9]
  PIN sum[0]
    DIRECTION OUTPUT ;
    USE SIGNAL ;
    PORT
      LAYER M4 ;
        RECT  189.996 12.96 190.08 12.984 ;
    END
  END sum[0]
  PIN sum[100]
    DIRECTION OUTPUT ;
    USE SIGNAL ;
    PORT
      LAYER M4 ;
        RECT  189.996 156.96 190.08 156.984 ;
    END
  END sum[100]
  PIN sum[101]
    DIRECTION OUTPUT ;
    USE SIGNAL ;
    PORT
      LAYER M4 ;
        RECT  189.996 158.4 190.08 158.424 ;
    END
  END sum[101]
  PIN sum[102]
    DIRECTION OUTPUT ;
    USE SIGNAL ;
    PORT
      LAYER M4 ;
        RECT  189.996 159.84 190.08 159.864 ;
    END
  END sum[102]
  PIN sum[103]
    DIRECTION OUTPUT ;
    USE SIGNAL ;
    PORT
      LAYER M4 ;
        RECT  189.996 161.28 190.08 161.304 ;
    END
  END sum[103]
  PIN sum[104]
    DIRECTION OUTPUT ;
    USE SIGNAL ;
    PORT
      LAYER M4 ;
        RECT  189.996 162.72 190.08 162.744 ;
    END
  END sum[104]
  PIN sum[105]
    DIRECTION OUTPUT ;
    USE SIGNAL ;
    PORT
      LAYER M4 ;
        RECT  189.996 164.16 190.08 164.184 ;
    END
  END sum[105]
  PIN sum[106]
    DIRECTION OUTPUT ;
    USE SIGNAL ;
    PORT
      LAYER M4 ;
        RECT  189.996 165.6 190.08 165.624 ;
    END
  END sum[106]
  PIN sum[107]
    DIRECTION OUTPUT ;
    USE SIGNAL ;
    PORT
      LAYER M4 ;
        RECT  189.996 167.04 190.08 167.064 ;
    END
  END sum[107]
  PIN sum[108]
    DIRECTION OUTPUT ;
    USE SIGNAL ;
    PORT
      LAYER M4 ;
        RECT  189.996 168.48 190.08 168.504 ;
    END
  END sum[108]
  PIN sum[109]
    DIRECTION OUTPUT ;
    USE SIGNAL ;
    PORT
      LAYER M4 ;
        RECT  189.996 169.92 190.08 169.944 ;
    END
  END sum[109]
  PIN sum[10]
    DIRECTION OUTPUT ;
    USE SIGNAL ;
    PORT
      LAYER M4 ;
        RECT  189.996 27.36 190.08 27.384 ;
    END
  END sum[10]
  PIN sum[110]
    DIRECTION OUTPUT ;
    USE SIGNAL ;
    PORT
      LAYER M4 ;
        RECT  189.996 171.36 190.08 171.384 ;
    END
  END sum[110]
  PIN sum[111]
    DIRECTION OUTPUT ;
    USE SIGNAL ;
    PORT
      LAYER M4 ;
        RECT  189.996 172.8 190.08 172.824 ;
    END
  END sum[111]
  PIN sum[112]
    DIRECTION OUTPUT ;
    USE SIGNAL ;
    PORT
      LAYER M4 ;
        RECT  189.996 174.24 190.08 174.264 ;
    END
  END sum[112]
  PIN sum[113]
    DIRECTION OUTPUT ;
    USE SIGNAL ;
    PORT
      LAYER M4 ;
        RECT  189.996 175.68 190.08 175.704 ;
    END
  END sum[113]
  PIN sum[114]
    DIRECTION OUTPUT ;
    USE SIGNAL ;
    PORT
      LAYER M4 ;
        RECT  189.996 177.12 190.08 177.144 ;
    END
  END sum[114]
  PIN sum[115]
    DIRECTION OUTPUT ;
    USE SIGNAL ;
    PORT
      LAYER M4 ;
        RECT  189.996 178.56 190.08 178.584 ;
    END
  END sum[115]
  PIN sum[116]
    DIRECTION OUTPUT ;
    USE SIGNAL ;
    PORT
      LAYER M4 ;
        RECT  189.996 180 190.08 180.024 ;
    END
  END sum[116]
  PIN sum[117]
    DIRECTION OUTPUT ;
    USE SIGNAL ;
    PORT
      LAYER M4 ;
        RECT  189.996 181.44 190.08 181.464 ;
    END
  END sum[117]
  PIN sum[118]
    DIRECTION OUTPUT ;
    USE SIGNAL ;
    PORT
      LAYER M4 ;
        RECT  189.996 182.88 190.08 182.904 ;
    END
  END sum[118]
  PIN sum[119]
    DIRECTION OUTPUT ;
    USE SIGNAL ;
    PORT
      LAYER M4 ;
        RECT  189.996 184.32 190.08 184.344 ;
    END
  END sum[119]
  PIN sum[11]
    DIRECTION OUTPUT ;
    USE SIGNAL ;
    PORT
      LAYER M4 ;
        RECT  189.996 28.8 190.08 28.824 ;
    END
  END sum[11]
  PIN sum[120]
    DIRECTION OUTPUT ;
    USE SIGNAL ;
    PORT
      LAYER M4 ;
        RECT  189.996 185.76 190.08 185.784 ;
    END
  END sum[120]
  PIN sum[121]
    DIRECTION OUTPUT ;
    USE SIGNAL ;
    PORT
      LAYER M4 ;
        RECT  189.996 187.2 190.08 187.224 ;
    END
  END sum[121]
  PIN sum[122]
    DIRECTION OUTPUT ;
    USE SIGNAL ;
    PORT
      LAYER M4 ;
        RECT  189.996 188.64 190.08 188.664 ;
    END
  END sum[122]
  PIN sum[123]
    DIRECTION OUTPUT ;
    USE SIGNAL ;
    PORT
      LAYER M4 ;
        RECT  189.996 190.08 190.08 190.104 ;
    END
  END sum[123]
  PIN sum[124]
    DIRECTION OUTPUT ;
    USE SIGNAL ;
    PORT
      LAYER M4 ;
        RECT  189.996 191.52 190.08 191.544 ;
    END
  END sum[124]
  PIN sum[125]
    DIRECTION OUTPUT ;
    USE SIGNAL ;
    PORT
      LAYER M4 ;
        RECT  189.996 192.96 190.08 192.984 ;
    END
  END sum[125]
  PIN sum[126]
    DIRECTION OUTPUT ;
    USE SIGNAL ;
    PORT
      LAYER M4 ;
        RECT  189.996 194.4 190.08 194.424 ;
    END
  END sum[126]
  PIN sum[127]
    DIRECTION OUTPUT ;
    USE SIGNAL ;
    PORT
      LAYER M4 ;
        RECT  189.996 195.84 190.08 195.864 ;
    END
  END sum[127]
  PIN sum[12]
    DIRECTION OUTPUT ;
    USE SIGNAL ;
    PORT
      LAYER M4 ;
        RECT  189.996 30.24 190.08 30.264 ;
    END
  END sum[12]
  PIN sum[13]
    DIRECTION OUTPUT ;
    USE SIGNAL ;
    PORT
      LAYER M4 ;
        RECT  189.996 31.68 190.08 31.704 ;
    END
  END sum[13]
  PIN sum[14]
    DIRECTION OUTPUT ;
    USE SIGNAL ;
    PORT
      LAYER M4 ;
        RECT  189.996 33.12 190.08 33.144 ;
    END
  END sum[14]
  PIN sum[15]
    DIRECTION OUTPUT ;
    USE SIGNAL ;
    PORT
      LAYER M4 ;
        RECT  189.996 34.56 190.08 34.584 ;
    END
  END sum[15]
  PIN sum[16]
    DIRECTION OUTPUT ;
    USE SIGNAL ;
    PORT
      LAYER M4 ;
        RECT  189.996 36 190.08 36.024 ;
    END
  END sum[16]
  PIN sum[17]
    DIRECTION OUTPUT ;
    USE SIGNAL ;
    PORT
      LAYER M4 ;
        RECT  189.996 37.44 190.08 37.464 ;
    END
  END sum[17]
  PIN sum[18]
    DIRECTION OUTPUT ;
    USE SIGNAL ;
    PORT
      LAYER M4 ;
        RECT  189.996 38.88 190.08 38.904 ;
    END
  END sum[18]
  PIN sum[19]
    DIRECTION OUTPUT ;
    USE SIGNAL ;
    PORT
      LAYER M4 ;
        RECT  189.996 40.32 190.08 40.344 ;
    END
  END sum[19]
  PIN sum[1]
    DIRECTION OUTPUT ;
    USE SIGNAL ;
    PORT
      LAYER M4 ;
        RECT  189.996 14.4 190.08 14.424 ;
    END
  END sum[1]
  PIN sum[20]
    DIRECTION OUTPUT ;
    USE SIGNAL ;
    PORT
      LAYER M4 ;
        RECT  189.996 41.76 190.08 41.784 ;
    END
  END sum[20]
  PIN sum[21]
    DIRECTION OUTPUT ;
    USE SIGNAL ;
    PORT
      LAYER M4 ;
        RECT  189.996 43.2 190.08 43.224 ;
    END
  END sum[21]
  PIN sum[22]
    DIRECTION OUTPUT ;
    USE SIGNAL ;
    PORT
      LAYER M4 ;
        RECT  189.996 44.64 190.08 44.664 ;
    END
  END sum[22]
  PIN sum[23]
    DIRECTION OUTPUT ;
    USE SIGNAL ;
    PORT
      LAYER M4 ;
        RECT  189.996 46.08 190.08 46.104 ;
    END
  END sum[23]
  PIN sum[24]
    DIRECTION OUTPUT ;
    USE SIGNAL ;
    PORT
      LAYER M4 ;
        RECT  189.996 47.52 190.08 47.544 ;
    END
  END sum[24]
  PIN sum[25]
    DIRECTION OUTPUT ;
    USE SIGNAL ;
    PORT
      LAYER M4 ;
        RECT  189.996 48.96 190.08 48.984 ;
    END
  END sum[25]
  PIN sum[26]
    DIRECTION OUTPUT ;
    USE SIGNAL ;
    PORT
      LAYER M4 ;
        RECT  189.996 50.4 190.08 50.424 ;
    END
  END sum[26]
  PIN sum[27]
    DIRECTION OUTPUT ;
    USE SIGNAL ;
    PORT
      LAYER M4 ;
        RECT  189.996 51.84 190.08 51.864 ;
    END
  END sum[27]
  PIN sum[28]
    DIRECTION OUTPUT ;
    USE SIGNAL ;
    PORT
      LAYER M4 ;
        RECT  189.996 53.28 190.08 53.304 ;
    END
  END sum[28]
  PIN sum[29]
    DIRECTION OUTPUT ;
    USE SIGNAL ;
    PORT
      LAYER M4 ;
        RECT  189.996 54.72 190.08 54.744 ;
    END
  END sum[29]
  PIN sum[2]
    DIRECTION OUTPUT ;
    USE SIGNAL ;
    PORT
      LAYER M4 ;
        RECT  189.996 15.84 190.08 15.864 ;
    END
  END sum[2]
  PIN sum[30]
    DIRECTION OUTPUT ;
    USE SIGNAL ;
    PORT
      LAYER M4 ;
        RECT  189.996 56.16 190.08 56.184 ;
    END
  END sum[30]
  PIN sum[31]
    DIRECTION OUTPUT ;
    USE SIGNAL ;
    PORT
      LAYER M4 ;
        RECT  189.996 57.6 190.08 57.624 ;
    END
  END sum[31]
  PIN sum[32]
    DIRECTION OUTPUT ;
    USE SIGNAL ;
    PORT
      LAYER M4 ;
        RECT  189.996 59.04 190.08 59.064 ;
    END
  END sum[32]
  PIN sum[33]
    DIRECTION OUTPUT ;
    USE SIGNAL ;
    PORT
      LAYER M4 ;
        RECT  189.996 60.48 190.08 60.504 ;
    END
  END sum[33]
  PIN sum[34]
    DIRECTION OUTPUT ;
    USE SIGNAL ;
    PORT
      LAYER M4 ;
        RECT  189.996 61.92 190.08 61.944 ;
    END
  END sum[34]
  PIN sum[35]
    DIRECTION OUTPUT ;
    USE SIGNAL ;
    PORT
      LAYER M4 ;
        RECT  189.996 63.36 190.08 63.384 ;
    END
  END sum[35]
  PIN sum[36]
    DIRECTION OUTPUT ;
    USE SIGNAL ;
    PORT
      LAYER M4 ;
        RECT  189.996 64.8 190.08 64.824 ;
    END
  END sum[36]
  PIN sum[37]
    DIRECTION OUTPUT ;
    USE SIGNAL ;
    PORT
      LAYER M4 ;
        RECT  189.996 66.24 190.08 66.264 ;
    END
  END sum[37]
  PIN sum[38]
    DIRECTION OUTPUT ;
    USE SIGNAL ;
    PORT
      LAYER M4 ;
        RECT  189.996 67.68 190.08 67.704 ;
    END
  END sum[38]
  PIN sum[39]
    DIRECTION OUTPUT ;
    USE SIGNAL ;
    PORT
      LAYER M4 ;
        RECT  189.996 69.12 190.08 69.144 ;
    END
  END sum[39]
  PIN sum[3]
    DIRECTION OUTPUT ;
    USE SIGNAL ;
    PORT
      LAYER M4 ;
        RECT  189.996 17.28 190.08 17.304 ;
    END
  END sum[3]
  PIN sum[40]
    DIRECTION OUTPUT ;
    USE SIGNAL ;
    PORT
      LAYER M4 ;
        RECT  189.996 70.56 190.08 70.584 ;
    END
  END sum[40]
  PIN sum[41]
    DIRECTION OUTPUT ;
    USE SIGNAL ;
    PORT
      LAYER M4 ;
        RECT  189.996 72 190.08 72.024 ;
    END
  END sum[41]
  PIN sum[42]
    DIRECTION OUTPUT ;
    USE SIGNAL ;
    PORT
      LAYER M4 ;
        RECT  189.996 73.44 190.08 73.464 ;
    END
  END sum[42]
  PIN sum[43]
    DIRECTION OUTPUT ;
    USE SIGNAL ;
    PORT
      LAYER M4 ;
        RECT  189.996 74.88 190.08 74.904 ;
    END
  END sum[43]
  PIN sum[44]
    DIRECTION OUTPUT ;
    USE SIGNAL ;
    PORT
      LAYER M4 ;
        RECT  189.996 76.32 190.08 76.344 ;
    END
  END sum[44]
  PIN sum[45]
    DIRECTION OUTPUT ;
    USE SIGNAL ;
    PORT
      LAYER M4 ;
        RECT  189.996 77.76 190.08 77.784 ;
    END
  END sum[45]
  PIN sum[46]
    DIRECTION OUTPUT ;
    USE SIGNAL ;
    PORT
      LAYER M4 ;
        RECT  189.996 79.2 190.08 79.224 ;
    END
  END sum[46]
  PIN sum[47]
    DIRECTION OUTPUT ;
    USE SIGNAL ;
    PORT
      LAYER M4 ;
        RECT  189.996 80.64 190.08 80.664 ;
    END
  END sum[47]
  PIN sum[48]
    DIRECTION OUTPUT ;
    USE SIGNAL ;
    PORT
      LAYER M4 ;
        RECT  189.996 82.08 190.08 82.104 ;
    END
  END sum[48]
  PIN sum[49]
    DIRECTION OUTPUT ;
    USE SIGNAL ;
    PORT
      LAYER M4 ;
        RECT  189.996 83.52 190.08 83.544 ;
    END
  END sum[49]
  PIN sum[4]
    DIRECTION OUTPUT ;
    USE SIGNAL ;
    PORT
      LAYER M4 ;
        RECT  189.996 18.72 190.08 18.744 ;
    END
  END sum[4]
  PIN sum[50]
    DIRECTION OUTPUT ;
    USE SIGNAL ;
    PORT
      LAYER M4 ;
        RECT  189.996 84.96 190.08 84.984 ;
    END
  END sum[50]
  PIN sum[51]
    DIRECTION OUTPUT ;
    USE SIGNAL ;
    PORT
      LAYER M4 ;
        RECT  189.996 86.4 190.08 86.424 ;
    END
  END sum[51]
  PIN sum[52]
    DIRECTION OUTPUT ;
    USE SIGNAL ;
    PORT
      LAYER M4 ;
        RECT  189.996 87.84 190.08 87.864 ;
    END
  END sum[52]
  PIN sum[53]
    DIRECTION OUTPUT ;
    USE SIGNAL ;
    PORT
      LAYER M4 ;
        RECT  189.996 89.28 190.08 89.304 ;
    END
  END sum[53]
  PIN sum[54]
    DIRECTION OUTPUT ;
    USE SIGNAL ;
    PORT
      LAYER M4 ;
        RECT  189.996 90.72 190.08 90.744 ;
    END
  END sum[54]
  PIN sum[55]
    DIRECTION OUTPUT ;
    USE SIGNAL ;
    PORT
      LAYER M4 ;
        RECT  189.996 92.16 190.08 92.184 ;
    END
  END sum[55]
  PIN sum[56]
    DIRECTION OUTPUT ;
    USE SIGNAL ;
    PORT
      LAYER M4 ;
        RECT  189.996 93.6 190.08 93.624 ;
    END
  END sum[56]
  PIN sum[57]
    DIRECTION OUTPUT ;
    USE SIGNAL ;
    PORT
      LAYER M4 ;
        RECT  189.996 95.04 190.08 95.064 ;
    END
  END sum[57]
  PIN sum[58]
    DIRECTION OUTPUT ;
    USE SIGNAL ;
    PORT
      LAYER M4 ;
        RECT  189.996 96.48 190.08 96.504 ;
    END
  END sum[58]
  PIN sum[59]
    DIRECTION OUTPUT ;
    USE SIGNAL ;
    PORT
      LAYER M4 ;
        RECT  189.996 97.92 190.08 97.944 ;
    END
  END sum[59]
  PIN sum[5]
    DIRECTION OUTPUT ;
    USE SIGNAL ;
    PORT
      LAYER M4 ;
        RECT  189.996 20.16 190.08 20.184 ;
    END
  END sum[5]
  PIN sum[60]
    DIRECTION OUTPUT ;
    USE SIGNAL ;
    PORT
      LAYER M4 ;
        RECT  189.996 99.36 190.08 99.384 ;
    END
  END sum[60]
  PIN sum[61]
    DIRECTION OUTPUT ;
    USE SIGNAL ;
    PORT
      LAYER M4 ;
        RECT  189.996 100.8 190.08 100.824 ;
    END
  END sum[61]
  PIN sum[62]
    DIRECTION OUTPUT ;
    USE SIGNAL ;
    PORT
      LAYER M4 ;
        RECT  189.996 102.24 190.08 102.264 ;
    END
  END sum[62]
  PIN sum[63]
    DIRECTION OUTPUT ;
    USE SIGNAL ;
    PORT
      LAYER M4 ;
        RECT  189.996 103.68 190.08 103.704 ;
    END
  END sum[63]
  PIN sum[64]
    DIRECTION OUTPUT ;
    USE SIGNAL ;
    PORT
      LAYER M4 ;
        RECT  189.996 105.12 190.08 105.144 ;
    END
  END sum[64]
  PIN sum[65]
    DIRECTION OUTPUT ;
    USE SIGNAL ;
    PORT
      LAYER M4 ;
        RECT  189.996 106.56 190.08 106.584 ;
    END
  END sum[65]
  PIN sum[66]
    DIRECTION OUTPUT ;
    USE SIGNAL ;
    PORT
      LAYER M4 ;
        RECT  189.996 108 190.08 108.024 ;
    END
  END sum[66]
  PIN sum[67]
    DIRECTION OUTPUT ;
    USE SIGNAL ;
    PORT
      LAYER M4 ;
        RECT  189.996 109.44 190.08 109.464 ;
    END
  END sum[67]
  PIN sum[68]
    DIRECTION OUTPUT ;
    USE SIGNAL ;
    PORT
      LAYER M4 ;
        RECT  189.996 110.88 190.08 110.904 ;
    END
  END sum[68]
  PIN sum[69]
    DIRECTION OUTPUT ;
    USE SIGNAL ;
    PORT
      LAYER M4 ;
        RECT  189.996 112.32 190.08 112.344 ;
    END
  END sum[69]
  PIN sum[6]
    DIRECTION OUTPUT ;
    USE SIGNAL ;
    PORT
      LAYER M4 ;
        RECT  189.996 21.6 190.08 21.624 ;
    END
  END sum[6]
  PIN sum[70]
    DIRECTION OUTPUT ;
    USE SIGNAL ;
    PORT
      LAYER M4 ;
        RECT  189.996 113.76 190.08 113.784 ;
    END
  END sum[70]
  PIN sum[71]
    DIRECTION OUTPUT ;
    USE SIGNAL ;
    PORT
      LAYER M4 ;
        RECT  189.996 115.2 190.08 115.224 ;
    END
  END sum[71]
  PIN sum[72]
    DIRECTION OUTPUT ;
    USE SIGNAL ;
    PORT
      LAYER M4 ;
        RECT  189.996 116.64 190.08 116.664 ;
    END
  END sum[72]
  PIN sum[73]
    DIRECTION OUTPUT ;
    USE SIGNAL ;
    PORT
      LAYER M4 ;
        RECT  189.996 118.08 190.08 118.104 ;
    END
  END sum[73]
  PIN sum[74]
    DIRECTION OUTPUT ;
    USE SIGNAL ;
    PORT
      LAYER M4 ;
        RECT  189.996 119.52 190.08 119.544 ;
    END
  END sum[74]
  PIN sum[75]
    DIRECTION OUTPUT ;
    USE SIGNAL ;
    PORT
      LAYER M4 ;
        RECT  189.996 120.96 190.08 120.984 ;
    END
  END sum[75]
  PIN sum[76]
    DIRECTION OUTPUT ;
    USE SIGNAL ;
    PORT
      LAYER M4 ;
        RECT  189.996 122.4 190.08 122.424 ;
    END
  END sum[76]
  PIN sum[77]
    DIRECTION OUTPUT ;
    USE SIGNAL ;
    PORT
      LAYER M4 ;
        RECT  189.996 123.84 190.08 123.864 ;
    END
  END sum[77]
  PIN sum[78]
    DIRECTION OUTPUT ;
    USE SIGNAL ;
    PORT
      LAYER M4 ;
        RECT  189.996 125.28 190.08 125.304 ;
    END
  END sum[78]
  PIN sum[79]
    DIRECTION OUTPUT ;
    USE SIGNAL ;
    PORT
      LAYER M4 ;
        RECT  189.996 126.72 190.08 126.744 ;
    END
  END sum[79]
  PIN sum[7]
    DIRECTION OUTPUT ;
    USE SIGNAL ;
    PORT
      LAYER M4 ;
        RECT  189.996 23.04 190.08 23.064 ;
    END
  END sum[7]
  PIN sum[80]
    DIRECTION OUTPUT ;
    USE SIGNAL ;
    PORT
      LAYER M4 ;
        RECT  189.996 128.16 190.08 128.184 ;
    END
  END sum[80]
  PIN sum[81]
    DIRECTION OUTPUT ;
    USE SIGNAL ;
    PORT
      LAYER M4 ;
        RECT  189.996 129.6 190.08 129.624 ;
    END
  END sum[81]
  PIN sum[82]
    DIRECTION OUTPUT ;
    USE SIGNAL ;
    PORT
      LAYER M4 ;
        RECT  189.996 131.04 190.08 131.064 ;
    END
  END sum[82]
  PIN sum[83]
    DIRECTION OUTPUT ;
    USE SIGNAL ;
    PORT
      LAYER M4 ;
        RECT  189.996 132.48 190.08 132.504 ;
    END
  END sum[83]
  PIN sum[84]
    DIRECTION OUTPUT ;
    USE SIGNAL ;
    PORT
      LAYER M4 ;
        RECT  189.996 133.92 190.08 133.944 ;
    END
  END sum[84]
  PIN sum[85]
    DIRECTION OUTPUT ;
    USE SIGNAL ;
    PORT
      LAYER M4 ;
        RECT  189.996 135.36 190.08 135.384 ;
    END
  END sum[85]
  PIN sum[86]
    DIRECTION OUTPUT ;
    USE SIGNAL ;
    PORT
      LAYER M4 ;
        RECT  189.996 136.8 190.08 136.824 ;
    END
  END sum[86]
  PIN sum[87]
    DIRECTION OUTPUT ;
    USE SIGNAL ;
    PORT
      LAYER M4 ;
        RECT  189.996 138.24 190.08 138.264 ;
    END
  END sum[87]
  PIN sum[88]
    DIRECTION OUTPUT ;
    USE SIGNAL ;
    PORT
      LAYER M4 ;
        RECT  189.996 139.68 190.08 139.704 ;
    END
  END sum[88]
  PIN sum[89]
    DIRECTION OUTPUT ;
    USE SIGNAL ;
    PORT
      LAYER M4 ;
        RECT  189.996 141.12 190.08 141.144 ;
    END
  END sum[89]
  PIN sum[8]
    DIRECTION OUTPUT ;
    USE SIGNAL ;
    PORT
      LAYER M4 ;
        RECT  189.996 24.48 190.08 24.504 ;
    END
  END sum[8]
  PIN sum[90]
    DIRECTION OUTPUT ;
    USE SIGNAL ;
    PORT
      LAYER M4 ;
        RECT  189.996 142.56 190.08 142.584 ;
    END
  END sum[90]
  PIN sum[91]
    DIRECTION OUTPUT ;
    USE SIGNAL ;
    PORT
      LAYER M4 ;
        RECT  189.996 144 190.08 144.024 ;
    END
  END sum[91]
  PIN sum[92]
    DIRECTION OUTPUT ;
    USE SIGNAL ;
    PORT
      LAYER M4 ;
        RECT  189.996 145.44 190.08 145.464 ;
    END
  END sum[92]
  PIN sum[93]
    DIRECTION OUTPUT ;
    USE SIGNAL ;
    PORT
      LAYER M4 ;
        RECT  189.996 146.88 190.08 146.904 ;
    END
  END sum[93]
  PIN sum[94]
    DIRECTION OUTPUT ;
    USE SIGNAL ;
    PORT
      LAYER M4 ;
        RECT  189.996 148.32 190.08 148.344 ;
    END
  END sum[94]
  PIN sum[95]
    DIRECTION OUTPUT ;
    USE SIGNAL ;
    PORT
      LAYER M4 ;
        RECT  189.996 149.76 190.08 149.784 ;
    END
  END sum[95]
  PIN sum[96]
    DIRECTION OUTPUT ;
    USE SIGNAL ;
    PORT
      LAYER M4 ;
        RECT  189.996 151.2 190.08 151.224 ;
    END
  END sum[96]
  PIN sum[97]
    DIRECTION OUTPUT ;
    USE SIGNAL ;
    PORT
      LAYER M4 ;
        RECT  189.996 152.64 190.08 152.664 ;
    END
  END sum[97]
  PIN sum[98]
    DIRECTION OUTPUT ;
    USE SIGNAL ;
    PORT
      LAYER M4 ;
        RECT  189.996 154.08 190.08 154.104 ;
    END
  END sum[98]
  PIN sum[99]
    DIRECTION OUTPUT ;
    USE SIGNAL ;
    PORT
      LAYER M4 ;
        RECT  189.996 155.52 190.08 155.544 ;
    END
  END sum[99]
  PIN sum[9]
    DIRECTION OUTPUT ;
    USE SIGNAL ;
    PORT
      LAYER M4 ;
        RECT  189.996 25.92 190.08 25.944 ;
    END
  END sum[9]
  PIN v_out
    DIRECTION OUTPUT ;
    USE SIGNAL ;
    PORT
      LAYER M4 ;
        RECT  189.996 197.28 190.08 197.304 ;
    END
  END v_out
  PIN VDD
    DIRECTION INOUT ;
    USE POWER ;
    PORT
      LAYER M5 ;
        RECT  183.636 4.311 183.756 207.369 ;
        RECT  179.316 4.311 179.436 207.369 ;
        RECT  174.996 4.311 175.116 207.369 ;
        RECT  170.676 4.311 170.796 207.369 ;
        RECT  166.356 4.311 166.476 207.369 ;
        RECT  162.036 4.311 162.156 207.369 ;
        RECT  157.716 4.311 157.836 207.369 ;
        RECT  153.396 4.311 153.516 207.369 ;
        RECT  149.076 4.311 149.196 207.369 ;
        RECT  144.756 4.311 144.876 207.369 ;
        RECT  140.436 4.311 140.556 207.369 ;
        RECT  136.116 4.311 136.236 207.369 ;
        RECT  131.796 4.311 131.916 207.369 ;
        RECT  127.476 4.311 127.596 207.369 ;
        RECT  123.156 4.311 123.276 207.369 ;
        RECT  118.836 4.311 118.956 207.369 ;
        RECT  114.516 4.311 114.636 207.369 ;
        RECT  110.196 4.311 110.316 207.369 ;
        RECT  105.876 4.311 105.996 207.369 ;
        RECT  101.556 4.311 101.676 207.369 ;
        RECT  97.236 4.311 97.356 207.369 ;
        RECT  92.916 4.311 93.036 207.369 ;
        RECT  88.596 4.311 88.716 207.369 ;
        RECT  84.276 4.311 84.396 207.369 ;
        RECT  79.956 4.311 80.076 207.369 ;
        RECT  75.636 4.311 75.756 207.369 ;
        RECT  71.316 4.311 71.436 207.369 ;
        RECT  66.996 4.311 67.116 207.369 ;
        RECT  62.676 4.311 62.796 207.369 ;
        RECT  58.356 4.311 58.476 207.369 ;
        RECT  54.036 4.311 54.156 207.369 ;
        RECT  49.716 4.311 49.836 207.369 ;
        RECT  45.396 4.311 45.516 207.369 ;
        RECT  41.076 4.311 41.196 207.369 ;
        RECT  36.756 4.311 36.876 207.369 ;
        RECT  32.436 4.311 32.556 207.369 ;
        RECT  28.116 4.311 28.236 207.369 ;
        RECT  23.796 4.311 23.916 207.369 ;
        RECT  19.476 4.311 19.596 207.369 ;
        RECT  15.156 4.311 15.276 207.369 ;
        RECT  10.836 4.311 10.956 207.369 ;
        RECT  6.516 4.311 6.636 207.369 ;
    END
  END VDD
  PIN VSS
    DIRECTION INOUT ;
    USE GROUND ;
    PORT
      LAYER M5 ;
        RECT  183.444 4.297 183.564 207.383 ;
        RECT  179.124 4.297 179.244 207.383 ;
        RECT  174.804 4.297 174.924 207.383 ;
        RECT  170.484 4.297 170.604 207.383 ;
        RECT  166.164 4.297 166.284 207.383 ;
        RECT  161.844 4.297 161.964 207.383 ;
        RECT  157.524 4.297 157.644 207.383 ;
        RECT  153.204 4.297 153.324 207.383 ;
        RECT  148.884 4.297 149.004 207.383 ;
        RECT  144.564 4.297 144.684 207.383 ;
        RECT  140.244 4.297 140.364 207.383 ;
        RECT  135.924 4.297 136.044 207.383 ;
        RECT  131.604 4.297 131.724 207.383 ;
        RECT  127.284 4.297 127.404 207.383 ;
        RECT  122.964 4.297 123.084 207.383 ;
        RECT  118.644 4.297 118.764 207.383 ;
        RECT  114.324 4.297 114.444 207.383 ;
        RECT  110.004 4.297 110.124 207.383 ;
        RECT  105.684 4.297 105.804 207.383 ;
        RECT  101.364 4.297 101.484 207.383 ;
        RECT  97.044 4.297 97.164 207.383 ;
        RECT  92.724 4.297 92.844 207.383 ;
        RECT  88.404 4.297 88.524 207.383 ;
        RECT  84.084 4.297 84.204 207.383 ;
        RECT  79.764 4.297 79.884 207.383 ;
        RECT  75.444 4.297 75.564 207.383 ;
        RECT  71.124 4.297 71.244 207.383 ;
        RECT  66.804 4.297 66.924 207.383 ;
        RECT  62.484 4.297 62.604 207.383 ;
        RECT  58.164 4.297 58.284 207.383 ;
        RECT  53.844 4.297 53.964 207.383 ;
        RECT  49.524 4.297 49.644 207.383 ;
        RECT  45.204 4.297 45.324 207.383 ;
        RECT  40.884 4.297 41.004 207.383 ;
        RECT  36.564 4.297 36.684 207.383 ;
        RECT  32.244 4.297 32.364 207.383 ;
        RECT  27.924 4.297 28.044 207.383 ;
        RECT  23.604 4.297 23.724 207.383 ;
        RECT  19.284 4.297 19.404 207.383 ;
        RECT  14.964 4.297 15.084 207.383 ;
        RECT  10.644 4.297 10.764 207.383 ;
        RECT  6.324 4.297 6.444 207.383 ;
    END
  END VSS
  OBS
    LAYER RVTN ;
     RECT  0 0 190.08 207.383 ;
    LAYER RVTP ;
     RECT  0 0 190.08 207.383 ;
    LAYER M1 ;
     RECT  0 0 190.08 207.383 ;
    LAYER M2 ;
     RECT  0 0 190.08 207.383 ;
    LAYER M3 ;
     RECT  0 0 190.08 207.383 ;
    LAYER M4 ;
     RECT  0 0 190.08 207.383 ;
    LAYER M5 ;
     RECT  0 0 190.08 207.383 ;
  END
END ot_coll_fold_slice
END LIBRARY
